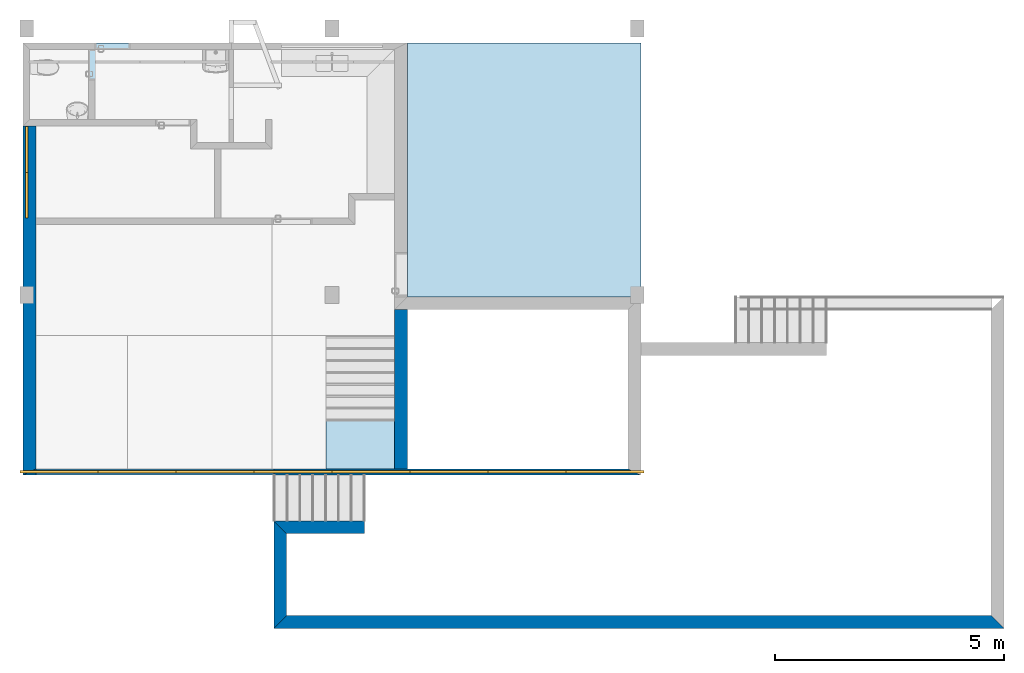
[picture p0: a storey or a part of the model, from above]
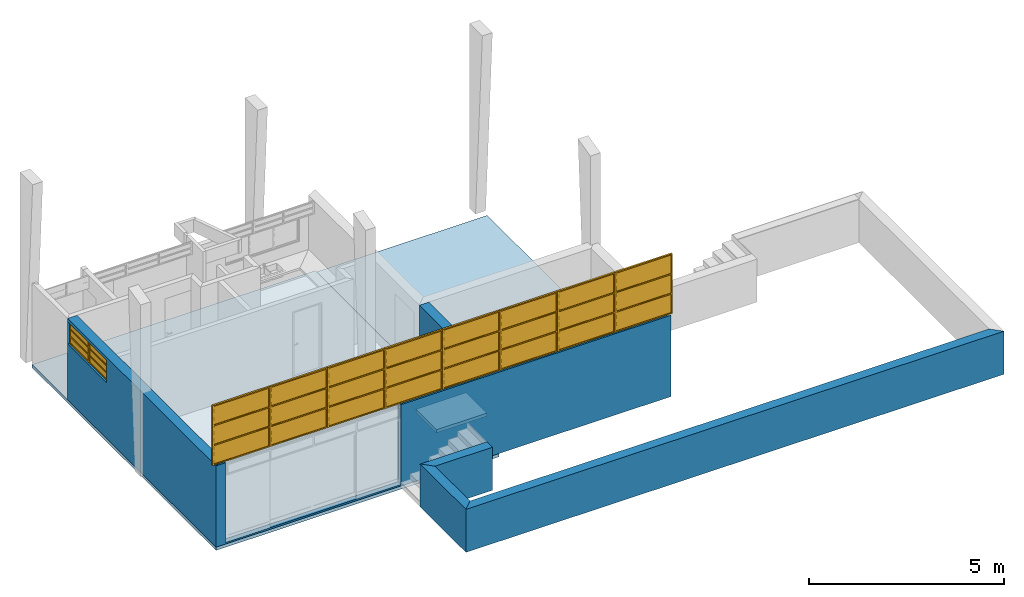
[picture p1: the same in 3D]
Properties of the parts of a building model (IFC2X3), part 1 of 2

# File
Description: ViewDefinition [CoordinationView_V2.0, QuantityTakeOffAddOnView], Option [Drawing Scale: 100.000000], Option [Elements to export: Entire project], Option [Partial Structure Display: Entire Model], Option [IFC Domain: All], Option [Structural Function: All Elements], Option [Convert Grid elements: On], Option [Convert IFC Annotations and ARCHICAD 2D elements: Off], Option [Convert 2D symbols of Doors and Windows: Off], Option [Export geometries that Participates in Collision Detection only: Off], Option [Split complex elements: Off], Option [Material Preservation: Explode where necessary], Option [Elements in Solid Element Operations: Extruded/revolved], Option [Elements with junctions: Extruded/revolved without junctions], Option [Slabs with slanted edge(s): Extruded], Option [IFC Site Location: At Project Origin], Option [Curtain Wall export mode: Container Element], Option [Railing export mode: Single Element], Option [Stair export mode: Container Element], Option [Properties To Export: All properties], Option [Space containment: Off], Option [Bounding Box: Off], Option [Geometry to type objects: Off], Option [Element Properties: Visible Only], Option [Building Material Properties: Off], Option [Element Parameters: Off], Option [Component Parameters: All], Option [IFC Base Quantities: On], Option [Door Window Parameters: On], Option [IFC Space boundaries: Off], Option [ARCHICAD Zone Categories as IFC Space classification data: Off], Option [Element Classifications: On]
File name: D:\Documents\FAU\ICs\PUB 2019-2020\PUB 2019-2020 Vanessa\Residência Olga Baeta.ifc
Time: 2021-04-10T14:19:01
Author: Architect
Organization: Building Designer Office
Written by: The EXPRESS Data Manager Version 5.02.0100.09 : 26 Sep 2013
Made in: IFC file generated by GRAPHISOFT ARCHICAD 23.0.0 BRA FULL Windows version (IFC add-on version: 3003 BRA FULL).
Authorization: The authorising person

# IfcSite, Local
RefLatitude: -23, -34, -3, -510000; RefLongitude: -46, -42, -34, -970000; RefElevation: 727000 mm
BaseQuantities - GrossPerimeter: 0 mm; GrossArea: 0 m2

# IfcBuilding, Construção
Classification: En_45_10_39 Casa isolada (NBR 15965-6)
BaseQuantities - GrossFloorArea: 216.281 m2

# IfcBuildingStorey (5)
In: Construção
Name | Elevation (mm) | NetHeight (mm) = GrossHeight (mm) = Height (mm) | GrossFloorArea (m2)
Fundação | -1500 | 1500 | 0
Pavimento Térreo | 0 | 1300 | 108.55
Pavimento Intermediário | 1300 | 1750 | 19.7248
Primeiro Pavimento | 3050 | 2750 | 88.0063
Pavimento Cobertura | 5800 | 2000 | 0

# IfcSpace: Circulação (3)
InteriorOrExteriorSpace: INTERNAL
Pset_SpaceCommon - Category: Circulação
AC_Pset_RenovationAndPhasing - Renovation Status: To Be Demolished
BaseQuantities - FinishFloorHeight: 0 mm
Name | In | LongName | Classification | Height (mm) = FinishCeilingHeight (mm) = ClearHeight (mm) | GrossFloorArea (m2) = NetFloorArea (m2) = SpaceNetFloorAreaBOMA (m2) = SpaceUsableFloorAreaBOMA (m2) = GrossCeilingArea (m2) = NetCeilingArea (m2) | GrossWallArea (m2) | NetWallArea (m2) | GrossPerimeter (mm) = NetPerimeter (mm) | GrossVolume (m3) | NetVolume (m3)
12 | Pavimento Térreo | Escada | Zoneamento (Classificação ARCHICAD); 4A 16 01 04 Escada (NBR 15965-6) | 5702.19 | 7.7988 | 12.9045 | 12.9045 | 11180 | 44.4702 | 37.4836
13 | Pavimento Térreo | Hall de entrada | Zoneamento (Classificação ARCHICAD); 4A 16 04 07 Saguão (NBR 15965-6) | 5702.19 | 6.8922 | 15.7845 | 11.9205 | 12500 | 39.3006 | 37.7929
11 | Primeiro Pavimento | Hall | Zoneamento (Classificação ARCHICAD); 4A 16 04 01 Corredor (NBR 15965-6) | 2550 | 13.7149 | 41.9729 | 31.8509 | 21300 | 34.973 | 33.7969

# IfcSpace: Área de serviço (4)
In: Pavimento Térreo
InteriorOrExteriorSpace: INTERNAL
Pset_SpaceCommon - Category: Área de serviço
AC_Pset_RenovationAndPhasing - Renovation Status: To Be Demolished
BaseQuantities - Height: 3050 mm; FinishCeilingHeight: 3050 mm; FinishFloorHeight: 0 mm; ClearHeight: 3050 mm
Name | LongName | Classification | GrossFloorArea (m2) = NetFloorArea (m2) = SpaceNetFloorAreaBOMA (m2) = SpaceUsableFloorAreaBOMA (m2) = GrossCeilingArea (m2) = NetCeilingArea (m2) | GrossWallArea (m2) | NetWallArea (m2) | GrossPerimeter (mm) = NetPerimeter (mm) | GrossVolume (m3) = NetVolume (m3)
03 | Lavanderia | Zoneamento (Classificação ARCHICAD); 4A 19 04 04 Lavanderia (NBR 15965-6) | 4.8622 | 22.284 | 17.643 | 9940 | 14.8297
02 | Cozinha | Zoneamento (Classificação ARCHICAD); 4A 19 01 25 Cozinha (NBR 15965-6) | 12.6781 | 39.7484 | 37.9214 | 17667.6 | 38.6681
04 | Banheiro de Serviço | Zoneamento (Classificação ARCHICAD); 4A 19 04 07 Banheiro Residencial (NBR 15965-6) | 1.9866 | 13.856 | 12.449 | 5660 | 6.05913
05 | Dormitório de serviço | Zoneamento (Classificação ARCHICAD); 4A 19 01 01 Dormitório (NBR 15965-6) | 7.579 | 28.741 | 27.124 | 11820 | 23.116

# IfcSpace: Área externa, 01
In: Pavimento Térreo
LongName: Garagem; InteriorOrExteriorSpace: INTERNAL; Classification: Zoneamento (Classificação ARCHICAD); 4A 19 04 13 Garagem (NBR 15965-6)
Pset_SpaceCommon - Category: Área externa
AC_Pset_RenovationAndPhasing - Renovation Status: Existing
BaseQuantities - Height: 3050 mm; FinishCeilingHeight: 3050 mm; FinishFloorHeight: 0 mm; ClearHeight: 3050 mm; GrossFloorArea: 28.305 m2; NetFloorArea: 28.305 m2; SpaceNetFloorAreaBOMA: 28.305 m2; SpaceUsableFloorAreaBOMA: 28.305 m2; GrossCeilingArea: 28.305 m2; NetCeilingArea: 28.305 m2; GrossWallArea: 26.084 m2; NetWallArea: 24.047 m2; GrossPerimeter: 21300 mm; NetPerimeter: 21300 mm; GrossVolume: 86.3303 m3; NetVolume: 86.3303 m3

# IfcSpace: Área social (3)
InteriorOrExteriorSpace: INTERNAL
Pset_SpaceCommon - Category: Área social
AC_Pset_RenovationAndPhasing - Renovation Status: To Be Demolished
BaseQuantities - FinishFloorHeight: 0 mm
Name | In | LongName | Classification | Height (mm) = FinishCeilingHeight (mm) = ClearHeight (mm) | GrossFloorArea (m2) = NetFloorArea (m2) = SpaceNetFloorAreaBOMA (m2) = SpaceUsableFloorAreaBOMA (m2) = GrossCeilingArea (m2) = NetCeilingArea (m2) | GrossWallArea (m2) | NetWallArea (m2) | GrossPerimeter (mm) = NetPerimeter (mm) | GrossVolume (m3) | NetVolume (m3)
07 | Pavimento Térreo | Sala de jantar | 4A 19 01 10 Sala de Jantar (NBR 15965-6); Zoneamento (Classificação ARCHICAD) | 5702.19 | 12.5388 | 19.3545 | 19.3545 | 15180 | 71.4986 | 68.5475
06 | Pavimento Térreo | Sala de estar | Zoneamento (Classificação ARCHICAD); 4A 19 01 07 Sala de Estar (NBR 15965-6) | 5702.19 | 15.0156 | 7.6785 | 7.6785 | 16140 | 85.6218 | 72.17
08 | Pavimento Intermediário | Escritório | Zoneamento (Classificação ARCHICAD); 4A 19 01 19 Escritório Residencial (NBR 15965-6) | 4201.52 | 16.7736 | 21.63 | 20.33 | 16600 | 70.4745 | 60.0031

# IfcSpace: Área íntima (6)
In: Primeiro Pavimento
InteriorOrExteriorSpace: INTERNAL
Pset_SpaceCommon - Category: Área íntima
AC_Pset_RenovationAndPhasing - Renovation Status: To Be Demolished
BaseQuantities - Height: 2550 mm; FinishCeilingHeight: 2550 mm; FinishFloorHeight: 0 mm; ClearHeight: 2550 mm
Name | LongName | Classification | GrossFloorArea (m2) = NetFloorArea (m2) = SpaceNetFloorAreaBOMA (m2) = SpaceUsableFloorAreaBOMA (m2) = GrossCeilingArea (m2) = NetCeilingArea (m2) | GrossWallArea (m2) | NetWallArea (m2) | GrossPerimeter (mm) = NetPerimeter (mm) | GrossVolume (m3) | NetVolume (m3)
15 | Dormitório 2 | Zoneamento (Classificação ARCHICAD); 4A 19 01 01 Dormitório (NBR 15965-6) | 12.098 | 37.4595 | 32.2125 | 14690 | 30.8498 | 30.8498
16 | Dormitório 3 | Zoneamento (Classificação ARCHICAD); 4A 19 01 01 Dormitório (NBR 15965-6) | 12.098 | 36.7241 | 31.4771 | 14690 | 30.8498 | 30.8498
09 | Dormitório 1 | Zoneamento (Classificação ARCHICAD); 4A 19 01 01 Dormitório (NBR 15965-6) | 18.0622 | 42.2238 | 36.9768 | 18220 | 46.0586 | 45.5784
14 | Banheiro 2 | Zoneamento (Classificação ARCHICAD); 4A 19 04 07 Banheiro Residencial (NBR 15965-6) | 5.5536 | 20.046 | 18.0914 | 9500 | 14.1617 | 14.125
17 | Dormitório 4 | Zoneamento (Classificação ARCHICAD); 4A 19 01 01 Dormitório (NBR 15965-6) | 11.1372 | 37.3616 | 32.1146 | 14940 | 28.3999 | 28.3999
10 | Banheiro 1 | Zoneamento (Classificação ARCHICAD); 4A 19 04 07 Banheiro Residencial (NBR 15965-6) | 4.694 | 18.6336 | 16.679 | 10560 | 11.9697 | 10.6472

# IfcBeam: Concreto Armado - Estrutural 100 x 300 (21)
In: Primeiro Pavimento
Description: Viga-interior-generico-in_loco-concreto_armado-100mm-300mm; Classification: 3E 12 06 02 00 Viga (NBR 15965-5); EF_20_10 Superstructure (Uniclass 2015); Viga (Classificação ARCHICAD); Material: Concreto Armado - Estrutural
AC_Pset_RenovationAndPhasing - Renovation Status: Existing
Pset_BeamCommon - LoadBearing: yes; IsExternal: no; Reference: Concreto Armado - Estrutural 100 x 300
Component Properties - Component 1, Tipo de Componente: Núcleo
BaseQuantities - Width: 100 mm; Depth: 300 mm; CrossSectionArea: 0.03 m2
Component Quantities - Component 1, Espessura da Camada: 100 mm; Component 1, Altura do Componente Retangular: 300 mm; Component 1, Largura do Componente Retangular: 100 mm; Component 1, Área de Seção Transversal do Componente: 0.03 m2
Name | Component 1, Carbono Incorporado | Component 1, Energia Incorporada (MJ) | NetSurfaceAreaExtrudedSides (m2) = OuterSurfaceArea (m2) | Length (mm) | TotalSurfaceArea (m2) = GrossSurfaceArea (m2) = NetSurfaceArea (m2) | GrossVolume (m3) = NetVolume (m3) = Component 1, Volume da Camada/ Componente (m3) | Component 1, Massa (kg) | Component 1, Área Projetada Componente/Camada (m2)
V13 | 218.497 (kgCO₂) | 2103.71 | 10.032 | 12540 | 10.092 | 0.3762 | 902.88 | 3.762
15 x V13 | 225.467 (kgCO₂) | 2170.81 | 10.352 | 12940 | 10.412 | 0.3882 | 931.68 | 3.882
2 x V13 | 97.5744 (kgCO₂) | 939.456 | 4.48 | 5600 | 4.54 | 0.168 | 403.2 | 1.68
V13 | 66.5597 (kgCO₂) | 640.843 | 3.056 | 3820 | 3.116 | 0.1146 | 275.04 | 1.146
V13 | 64.8173 (kgCO₂) | 624.067 | 2.976 | 3720 | 3.036 | 0.1116 | 267.84 | 1.116
V13 | 9.23472 (kgCO₂) | 88.9128 | 0.424 | 530 | 0.484 | 0.0159 | 38.16 | 0.159

# IfcBeam: Concreto Armado - Estrutural 220 x 360 (12)
In: Pavimento Cobertura
Description: Viga-interior-generico-in_loco-concreto_armado-220mm-360mm; Classification: 3E 12 06 02 00 Viga (NBR 15965-5); EF_20_10 Superstructure (Uniclass 2015); Viga (Classificação ARCHICAD); Material: Concreto Armado - Estrutural
AC_Pset_RenovationAndPhasing - Renovation Status: Existing
Pset_BeamCommon - LoadBearing: yes; IsExternal: no; Reference: Concreto Armado - Estrutural 220 x 360
Component Properties - Component 1, Tipo de Componente: Núcleo
BaseQuantities - Length: 6370 mm; Width: 220 mm; Depth: 360 mm; CrossSectionArea: 0.0792 m2
Component Quantities - Component 1, Espessura da Camada: 220 mm; Component 1, Altura do Componente Retangular: 360 mm; Component 1, Largura do Componente Retangular: 220 mm; Component 1, Área de Seção Transversal do Componente: 0.0792 m2
Name | Component 1, Carbono Incorporado | Component 1, Energia Incorporada (MJ) | NetSurfaceAreaExtrudedSides (m2) = OuterSurfaceArea (m2) | TotalSurfaceArea (m2) = GrossSurfaceArea (m2) = NetSurfaceArea (m2) | GrossVolume (m3) = NetVolume (m3) = Component 1, Volume da Camada/ Componente (m3) | Component 1, Massa (kg) | Component 1, Área Projetada Componente/Camada (m2)
10 x V13 | 283.622 (kgCO₂) | 2730.75 | 7.03326 | 7.19166 | 0.488331 | 1171.99 | 2.23585
2 x V13 | 282.665 (kgCO₂) | 2721.53 | 7.08492 | 7.24332 | 0.486683 | 1168.04 | 2.22008

# IfcBeam: Concreto Armado - Estrutural 250 x 300 (5)
In: Primeiro Pavimento
Description: viga-interior-concreto_armado-250mm-300mm; Classification: 3E 12 06 02 00 Viga (NBR 15965-5); EF_20_10 Superstructure (Uniclass 2015); Viga (Classificação ARCHICAD); Material: Concreto Armado - Estrutural
AC_Pset_RenovationAndPhasing - Renovation Status: Existing
Pset_BeamCommon - LoadBearing: yes; IsExternal: no; Reference: Concreto Armado - Estrutural 250 x 300
Component Properties - Component 1, Tipo de Componente: Núcleo
BaseQuantities - Width: 250 mm; Depth: 300 mm; CrossSectionArea: 0.075 m2
Component Quantities - Component 1, Espessura da Camada: 250 mm; Component 1, Altura do Componente Retangular: 300 mm; Component 1, Largura do Componente Retangular: 250 mm; Component 1, Área de Seção Transversal do Componente: 0.075 m2
Name | Component 1, Carbono Incorporado | Component 1, Energia Incorporada (MJ) | NetSurfaceAreaExtrudedSides (m2) = OuterSurfaceArea (m2) | Length (mm) | TotalSurfaceArea (m2) = GrossSurfaceArea (m2) = NetSurfaceArea (m2) | GrossVolume (m3) = NetVolume (m3) = Component 1, Volume da Camada/ Componente (m3) | Component 1, Massa (kg) | Component 1, Área Projetada Componente/Camada (m2)
V13 | 583.268 (kgCO₂) | 5615.77 | 14.729 | 13640 | 14.879 | 1.00425 | 2410.2 | 4.092
2 x V13 | 233.162 (kgCO₂) | 2244.91 | 5.86921 | 5530.17 | 6.01921 | 0.401451 | 963.481 | 1.65362
V13 | 567.083 (kgCO₂) | 5459.94 | 14.2733 | 13420.2 | 14.4233 | 0.976383 | 2343.32 | 4.02062
V13 | 164.597 (kgCO₂) | 1584.75 | 4.17862 | 4000 | 4.32862 | 0.283397 | 680.152 | 1.2

# IfcBeam: Concreto Armado - Estrutural 300 x 200 (6)
In: Pavimento Cobertura
Description: Viga-interior-generico-in_loco-concreto_armado-300mm-200mm; Classification: 3E 12 06 02 00 Viga (NBR 15965-5); EF_20_10 Superstructure (Uniclass 2015); Viga (Classificação ARCHICAD); Material: Concreto Armado - Estrutural
AC_Pset_RenovationAndPhasing - Renovation Status: Existing
Pset_BeamCommon - LoadBearing: yes; IsExternal: no; Reference: Concreto Armado - Estrutural 300 x 200
Component Properties - Component 1, Tipo de Componente: Núcleo
BaseQuantities - Width: 300 mm; Depth: 200 mm; CrossSectionArea: 0.06 m2
Component Quantities - Component 1, Espessura da Camada: 300 mm; Component 1, Altura do Componente Retangular: 200 mm; Component 1, Largura do Componente Retangular: 300 mm; Component 1, Área de Seção Transversal do Componente: 0.06 m2
Name | Component 1, Carbono Incorporado | Component 1, Energia Incorporada (MJ) | NetSurfaceAreaExtrudedSides (m2) = OuterSurfaceArea (m2) | Length (mm) | TotalSurfaceArea (m2) = GrossSurfaceArea (m2) = NetSurfaceArea (m2) | GrossVolume (m3) = NetVolume (m3) = Component 1, Volume da Camada/ Componente (m3) | Component 1, Massa (kg) | Component 1, Área Projetada Componente/Camada (m2)
3 x V10 | 81.3778 (kgCO₂) | 783.514 | 2.33522 | 2761.23 | 2.45522 | 0.140113 | 336.272 | 0.467045
3 x V11 | 271.547 (kgCO₂) | 2614.48 | 7.79232 | 8218.33 | 7.91232 | 0.467539 | 1122.09 | 1.55846

# IfcBeam: Concreto Armado - Estrutural 600 x 150 (4)
In: Pavimento Cobertura
Description: Viga-interior-generico-in_loco-concreto_armado-600mm-150mm; Classification: 3E 12 06 02 00 Viga (NBR 15965-5); EF_20_10 Superstructure (Uniclass 2015); Viga (Classificação ARCHICAD); Material: Concreto Armado - Estrutural
AC_Pset_RenovationAndPhasing - Renovation Status: Existing
Pset_BeamCommon - LoadBearing: yes; IsExternal: no; Reference: Concreto Armado - Estrutural 600 x 150
Component Properties - Component 1, Tipo de Componente: Núcleo
BaseQuantities - Width: 600 mm; Depth: 150 mm; CrossSectionArea: 0.09 m2
Component Quantities - Component 1, Espessura da Camada: 600 mm; Component 1, Altura do Componente Retangular: 150 mm; Component 1, Largura do Componente Retangular: 600 mm; Component 1, Área de Seção Transversal do Componente: 0.09 m2
Name | Component 1, Carbono Incorporado | Component 1, Energia Incorporada (MJ) | NetSurfaceAreaExtrudedSides (m2) = OuterSurfaceArea (m2) | Length (mm) | TotalSurfaceArea (m2) = GrossSurfaceArea (m2) = NetSurfaceArea (m2) | GrossVolume (m3) = NetVolume (m3) = Component 1, Volume da Camada/ Componente (m3) | Component 1, Massa (kg) | Component 1, Área Projetada Componente/Camada (m2)
2 x V19 | 157.211 (kgCO₂) | 1513.64 | 4.41566 | 3112.32 | 4.59566 | 0.27068 | 649.632 | 0.451133
2 x V21 | 442.464 (kgCO₂) | 4260.09 | 12.6013 | 8569.42 | 12.7813 | 0.761819 | 1828.37 | 1.2697

# IfcBeam: Concreto Armado - Estrutural 850 x 150 (2)
In: Pavimento Cobertura
Description: Viga-interior-generico-in_loco-concreto_armado-850mm-150mm; Classification: 3E 12 06 02 00 Viga (NBR 15965-5); EF_20_10 Superstructure (Uniclass 2015); Viga (Classificação ARCHICAD); Material: Concreto Armado - Estrutural
AC_Pset_RenovationAndPhasing - Renovation Status: Existing
Pset_BeamCommon - LoadBearing: yes; IsExternal: no; Reference: Concreto Armado - Estrutural 850 x 150
Component Properties - Component 1, Tipo de Componente: Núcleo
BaseQuantities - Width: 850 mm; Depth: 150 mm; CrossSectionArea: 0.1275 m2
Component Quantities - Component 1, Espessura da Camada: 850 mm; Component 1, Altura do Componente Retangular: 150 mm; Component 1, Largura do Componente Retangular: 850 mm; Component 1, Área de Seção Transversal do Componente: 0.1275 m2
Name | Component 1, Carbono Incorporado | Component 1, Energia Incorporada (MJ) | NetSurfaceAreaExtrudedSides (m2) = OuterSurfaceArea (m2) | Length (mm) | TotalSurfaceArea (m2) = GrossSurfaceArea (m2) = NetSurfaceArea (m2) | GrossVolume (m3) = NetVolume (m3) = Component 1, Volume da Camada/ Componente (m3) | Component 1, Massa (kg) | Component 1, Área Projetada Componente/Camada (m2)
V18 | 626.825 (kgCO₂) | 6035.13 | 16.7938 | 8569.42 | 17.0488 | 1.07924 | 2590.18 | 1.2697
V17 | 222.716 (kgCO₂) | 2144.33 | 5.87957 | 3112.32 | 6.13457 | 0.383463 | 920.312 | 0.451133

# IfcBeam: Madeiramento - Cobertura 50 x 10 (40)
In: Pavimento Cobertura
Description: ripa--generico-generico-madeira-50mm-10mm; Classification: Viga (Classificação ARCHICAD); EF_30_10 Roofs (Uniclass 2015); 3E 14 04 02 Telhado (NBR 15965-5); Material: Madeiramento - Cobertura
AC_Pset_RenovationAndPhasing - Renovation Status: Existing
Pset_BeamCommon - LoadBearing: yes; IsExternal: yes; Reference: Madeiramento - Cobertura 50 x 10
Component Properties - Component 1, Tipo de Componente: Núcleo
BaseQuantities - Length: 13640 mm; Width: 50 mm; Depth: 10 mm; CrossSectionArea: 0.0005 m2
Component Quantities - Component 1, Área Projetada Componente/Camada: 0.1364 m2; Component 1, Espessura da Camada: 50 mm; Component 1, Altura do Componente Retangular: 10 mm; Component 1, Largura do Componente Retangular: 50 mm; Component 1, Área de Seção Transversal do Componente: 0.0005 m2
Name | Component 1, Carbono Incorporado | Component 1, Energia Incorporada (MJ) | NetSurfaceAreaExtrudedSides (m2) = OuterSurfaceArea (m2) | TotalSurfaceArea (m2) = GrossSurfaceArea (m2) = NetSurfaceArea (m2) | GrossVolume (m3) = NetVolume (m3) = Component 1, Volume da Camada/ Componente (m3) | Component 1, Massa (kg)
2 x Ripa | 1.2231 (kgCO₂) | 33.975 | 1.6308 | 1.6318 | 0.006795 | 3.3975
38 x Ripa | 1.2276 (kgCO₂) | 34.1 | 1.6368 | 1.6378 | 0.00682 | 3.41

# IfcBeam: Madeiramento - Cobertura 50 x 60 (62)
In: Pavimento Cobertura
Description: caibro--generico-generico-madeira-50mm-60mm; Classification: Viga (Classificação ARCHICAD); EF_30_10 Roofs (Uniclass 2015); 3E 14 04 02 Telhado (NBR 15965-5); Material: Madeiramento - Cobertura
AC_Pset_RenovationAndPhasing - Renovation Status: Existing
Pset_BeamCommon - LoadBearing: yes; IsExternal: yes; Reference: Madeiramento - Cobertura 50 x 60
Component Properties - Component 1, Tipo de Componente: Núcleo
BaseQuantities - Width: 50 mm; Depth: 60 mm; CrossSectionArea: 0.003 m2
Component Quantities - Component 1, Espessura da Camada: 50 mm; Component 1, Altura do Componente Retangular: 60 mm; Component 1, Largura do Componente Retangular: 50 mm; Component 1, Área de Seção Transversal do Componente: 0.003 m2
Name | Component 1, Carbono Incorporado | Component 1, Energia Incorporada (MJ) | NetSurfaceAreaExtrudedSides (m2) = OuterSurfaceArea (m2) | Length (mm) | TotalSurfaceArea (m2) = GrossSurfaceArea (m2) = NetSurfaceArea (m2) | GrossVolume (m3) = NetVolume (m3) = Component 1, Volume da Camada/ Componente (m3) | Component 1, Massa (kg) | Component 1, Área Projetada Componente/Camada (m2)
10 x Caibro | 3.07809 (kgCO₂) | 85.5024 | 1.23852 | 5795 | 1.24452 | 0.0171005 | 8.55024 | 0.345126
Caibro | 4.59893 (kgCO₂) | 127.748 | 1.87364 | 8549.02 | 1.87964 | 0.0255496 | 12.7748 | 0.512492
2 x Caibro | 1.65345 (kgCO₂) | 45.9291 | 0.673626 | 3094.42 | 0.679626 | 0.00918581 | 4.59291 | 0.185216
24 x Caibro | 4.61782 (kgCO₂) | 128.273 | 1.88133 | 8566.48 | 1.88733 | 0.0256545 | 12.8273 | 0.513091
24 x Caibro | 1.67233 (kgCO₂) | 46.4537 | 0.68132 | 3111.87 | 0.68732 | 0.00929073 | 4.64537 | 0.185815
Caibro | 4.59893 (kgCO₂) | 127.748 | 1.87364 | 8549.02 | 1.87964 | 0.0255496 | 12.7748 | 0.512493

# IfcBuildingElementPart (66)
Name | In | Material | Carbono Incorporado | Energia Incorporada (MJ) | Tipo de Componente | Massa (kg) | Área Projetada Componente/Camada (m2) | Espessura da Camada (mm) = Largura do Componente Retangular (mm) | Altura do Componente Retangular (mm) | Área de Seção Transversal do Componente (m2) | Volume da Camada/ Componente (m3)
Reboco | Pavimento Térreo | Reboco | 19.7589 (kgCO₂) | 273.585 | Acabamento | 151.992 | 5.84584 | 20 | 1350 | 0.027 | 0.116917
Tijolo - Estrutural | Pavimento Térreo | Tijolo - Estrutural | 507.414 (kgCO₂) | 6342.67 | Núcleo | 2114.22 | 5.87284 | 240 | 1350 | 0.324 | 1.40948
Reboco | Pavimento Térreo | Reboco | 20.9453 (kgCO₂) | 290.012 | Acabamento | 161.118 | 6.19684 | 20 | 1350 | 0.027 | 0.123937
Reboco (1) | Primeiro Pavimento | Reboco (1) | 51.4628 (kgCO₂) | 712.562 | Acabamento | 395.868 | 15.2445 | 20 | 3211.87 | 0.0642375 | 0.304514
Tijolo - Estrutural (1) | Primeiro Pavimento | Tijolo - Estrutural (1) | 556.162 (kgCO₂) | 6952.02 | Núcleo | 2317.34 | 15.5437 | 100 | 3211.87 | 0.321187 | 1.54489
Reboco (1) | Primeiro Pavimento | Reboco (1) | 50.3556 (kgCO₂) | 697.231 | Acabamento | 387.35 | 14.9164 | 20 | 3211.87 | 0.0642375 | 0.297962
Reboco (1) | Primeiro Pavimento | Reboco (1) | 69.5168 (kgCO₂) | 962.541 | Acabamento | 534.745 | 20.6426 | 20 | 3211.87 | 0.0642375 | 0.411342
Tijolo - Estrutural (1) | Primeiro Pavimento | Tijolo - Estrutural (1) | 769.641 (kgCO₂) | 9620.51 | Núcleo | 3206.84 | 21.3789 | 100 | 3211.87 | 0.321187 | 2.13789
Reboco (1) | Primeiro Pavimento | Reboco (1) | 72.2607 (kgCO₂) | 1000.53 | Acabamento | 555.852 | 21.3789 | 20 | 3211.87 | 0.0642375 | 0.427578
Reboco (1) | Primeiro Pavimento | Reboco (1) | 26.5744 (kgCO₂) | 367.953 | Acabamento | 204.418 | 7.86881 | 20 | 3211.87 | 0.0642375 | 0.157245
Tijolo - Estrutural (1) | Primeiro Pavimento | Tijolo - Estrutural (1) | 301.648 (kgCO₂) | 3770.6 | Núcleo | 1256.87 | 8.4139 | 100 | 3211.87 | 0.321187 | 0.837911
Reboco (1) | Primeiro Pavimento | Reboco (1) | 28.6665 (kgCO₂) | 396.921 | Acabamento | 220.512 | 8.48822 | 20 | 3211.87 | 0.0642375 | 0.169624
2 x Reboco (1) | Primeiro Pavimento | Reboco (1) | 38.1169 (kgCO₂) | 527.772 | Acabamento | 293.207 | 11.2772 | 20 | 3211.87 | 0.0642375 | 0.225544
Tijolo - Estrutural (1) | Primeiro Pavimento | Tijolo - Estrutural (1) | 409.952 (kgCO₂) | 5124.4 | Núcleo | 1708.13 | 11.3876 | 100 | 3211.87 | 0.321187 | 1.13876
Reboco (1) | Primeiro Pavimento | Reboco (1) | 48.5939 (kgCO₂) | 672.839 | Acabamento | 373.8 | 14.3769 | 20 | 3211.87 | 0.0642375 | 0.287538
Tijolo - Estrutural (1) | Primeiro Pavimento | Tijolo - Estrutural (1) | 535.947 (kgCO₂) | 6699.34 | Núcleo | 2233.11 | 14.8874 | 100 | 3211.87 | 0.321187 | 1.48874
Reboco (1) | Primeiro Pavimento | Reboco (1) | 49.3738 (kgCO₂) | 683.638 | Acabamento | 379.799 | 14.6076 | 20 | 3211.87 | 0.0642375 | 0.292153
Reboco (1) | Primeiro Pavimento | Reboco (1) | 18.3303 (kgCO₂) | 253.804 | Acabamento | 141.002 | 5.42315 | 20 | 3211.87 | 0.0642375 | 0.108463
Tijolo - Estrutural (1) | Primeiro Pavimento | Tijolo - Estrutural (1) | 208.661 (kgCO₂) | 2608.26 | Núcleo | 869.421 | 5.79614 | 100 | 3211.87 | 0.321187 | 0.579614
Reboco (1) | Primeiro Pavimento | Reboco (1) | 19.621 (kgCO₂) | 271.676 | Acabamento | 150.931 | 5.80504 | 20 | 3211.87 | 0.0642375 | 0.116101
Reboco (1) | Primeiro Pavimento | Reboco (1) | 26.8015 (kgCO₂) | 371.097 | Acabamento | 206.165 | 7.93895 | 20 | 3211.87 | 0.0642375 | 0.158589
Tijolo - Estrutural (1) | Primeiro Pavimento | Tijolo - Estrutural (1) | 286.011 (kgCO₂) | 3575.14 | Núcleo | 1191.71 | 7.99213 | 100 | 3211.87 | 0.321187 | 0.794476
Reboco (1) | Primeiro Pavimento | Reboco (1) | 26.3337 (kgCO₂) | 364.621 | Acabamento | 202.567 | 7.80026 | 20 | 3211.87 | 0.0642375 | 0.155821
Reboco (1) | Primeiro Pavimento | Reboco (1) | 24.5278 (kgCO₂) | 339.615 | Acabamento | 188.675 | 7.26484 | 20 | 3211.87 | 0.0642375 | 0.145135
Tijolo - Estrutural (1) | Primeiro Pavimento | Tijolo - Estrutural (1) | 253.282 (kgCO₂) | 3166.03 | Núcleo | 1055.34 | 7.07464 | 100 | 3211.87 | 0.321187 | 0.703562
Reboco (1) | Primeiro Pavimento | Reboco (1) | 23.0209 (kgCO₂) | 318.751 | Acabamento | 177.084 | 6.81842 | 20 | 3211.87 | 0.0642375 | 0.136218
Reboco (1) | Primeiro Pavimento | Reboco (1) | 20.0006 (kgCO₂) | 276.931 | Acabamento | 153.851 | 5.91733 | 20 | 3211.87 | 0.0642375 | 0.118347
Tijolo - Estrutural (1) | Primeiro Pavimento | Tijolo - Estrutural (1) | 212.739 (kgCO₂) | 2659.24 | Núcleo | 886.412 | 5.90941 | 100 | 3211.87 | 0.321187 | 0.590941
Reboco (1) | Primeiro Pavimento | Reboco (1) | 18.7118 (kgCO₂) | 259.087 | Acabamento | 143.937 | 5.53605 | 20 | 3211.87 | 0.0642375 | 0.110721
Reboco (1) | Primeiro Pavimento | Reboco (1) | 7.34301 (kgCO₂) | 101.673 | Acabamento | 56.4847 | 2.17419 | 20 | 3211.87 | 0.0642375 | 0.0434498
Tijolo - Estrutural (1) | Primeiro Pavimento | Tijolo - Estrutural (1) | 68.6854 (kgCO₂) | 858.567 | Núcleo | 286.189 | 1.91541 | 100 | 3211.87 | 0.321187 | 0.190793
Reboco (1) | Primeiro Pavimento | Reboco (1) | 7.27425 (kgCO₂) | 100.72 | Acabamento | 55.9558 | 2.15384 | 20 | 3211.87 | 0.0642375 | 0.0430429
Reboco (1) | Primeiro Pavimento | Reboco (1) | 7.54194 (kgCO₂) | 104.427 | Acabamento | 58.0149 | 2.23134 | 20 | 3211.87 | 0.0642375 | 0.0446268
Tijolo - Estrutural (1) | Primeiro Pavimento | Tijolo - Estrutural (1) | 78.7207 (kgCO₂) | 984.008 | Núcleo | 328.003 | 2.18668 | 100 | 3211.87 | 0.321187 | 0.218668
Reboco (1) | Primeiro Pavimento | Reboco (1) | 6.63124 (kgCO₂) | 91.8171 | Acabamento | 51.0095 | 1.9619 | 20 | 3211.87 | 0.0642375 | 0.0392381
Reboco (1) | Primeiro Pavimento | Reboco (1) | 25.5089 (kgCO₂) | 353.2 | Acabamento | 196.222 | 7.55544 | 20 | 3211.87 | 0.0642375 | 0.15094
Tijolo - Estrutural (1) | Primeiro Pavimento | Tijolo - Estrutural (1) | 267.039 (kgCO₂) | 3337.99 | Núcleo | 1112.66 | 7.45889 | 100 | 3211.87 | 0.321187 | 0.741775
Reboco (1) | Primeiro Pavimento | Reboco (1) | 24.9329 (kgCO₂) | 345.225 | Acabamento | 191.792 | 7.38473 | 20 | 3211.87 | 0.0642375 | 0.147532
Reboco (1) | Primeiro Pavimento | Reboco (1) | 2.02544 (kgCO₂) | 28.0446 | Acabamento | 15.5803 | 0.599244 | 20 | 3211.87 | 0.0642375 | 0.0119849
Tijolo - Estrutural (1) | Primeiro Pavimento | Tijolo - Estrutural (1) | 23.202 (kgCO₂) | 290.025 | Núcleo | 96.6749 | 0.644499 | 100 | 3211.87 | 0.321187 | 0.0644499
Reboco (1) | Primeiro Pavimento | Reboco (1) | 2.93816 (kgCO₂) | 40.6823 | Acabamento | 22.6013 | 0.869279 | 20 | 3211.87 | 0.0642375 | 0.0173856
Reboco (1) | Primeiro Pavimento | Reboco (1) | 10.14 (kgCO₂) | 140.401 | Acabamento | 78.0003 | 3.00001 | 20 | 3211.87 | 0.0642375 | 0.0600002
Tijolo - Estrutural (1) | Primeiro Pavimento | Tijolo - Estrutural (1) | 118.336 (kgCO₂) | 1479.2 | Núcleo | 493.065 | 3.2871 | 100 | 3211.87 | 0.321187 | 0.32871
Reboco (1) | Primeiro Pavimento | Reboco (1) | 11.9837 (kgCO₂) | 165.928 | Acabamento | 92.1822 | 3.54547 | 20 | 3211.87 | 0.0642375 | 0.0709094
Reboco (1) | Primeiro Pavimento | Reboco (1) | 9.58675 (kgCO₂) | 132.74 | Acabamento | 73.7442 | 2.8406 | 20 | 3211.87 | 0.0642375 | 0.0567263
Tijolo - Estrutural (1) | Primeiro Pavimento | Tijolo - Estrutural (1) | 106.365 (kgCO₂) | 1329.56 | Núcleo | 443.186 | 2.97676 | 100 | 3211.87 | 0.321187 | 0.295457
Reboco (1) | Primeiro Pavimento | Reboco (1) | 9.0701 (kgCO₂) | 125.586 | Acabamento | 69.77 | 2.68765 | 20 | 3211.87 | 0.0642375 | 0.0536692
Reboco (1) | Primeiro Pavimento | Reboco (1) | 14.6991 (kgCO₂) | 203.526 | Acabamento | 113.07 | 4.34885 | 20 | 3211.87 | 0.0642375 | 0.0869769
Tijolo - Estrutural (1) | Primeiro Pavimento | Tijolo - Estrutural (1) | 157.435 (kgCO₂) | 1967.94 | Núcleo | 655.981 | 4.37321 | 100 | 3211.87 | 0.321187 | 0.437321
Reboco (1) | Primeiro Pavimento | Reboco (1) | 14.4128 (kgCO₂) | 199.562 | Acabamento | 110.868 | 4.26415 | 20 | 3211.87 | 0.0642375 | 0.0852829
2 x Reboco (1) | Primeiro Pavimento | Reboco (1) | 9.50169 (kgCO₂) | 131.562 | Acabamento | 73.0899 | 2.81115 | 20 | 4250 | 0.085 | 0.056223
Tijolo - Estrutural (1) | Primeiro Pavimento | Tijolo - Estrutural (1) | 61.9902 (kgCO₂) | 774.877 | Núcleo | 258.292 | 2.86992 | 60 | 4250 | 0.255 | 0.172195
Reboco (1) | Primeiro Pavimento | Reboco (1) | 3.4206 (kgCO₂) | 47.3622 | Acabamento | 26.3123 | 1.01201 | 20 | 4250 | 0.085 | 0.0202403
Tijolo - Estrutural (1) | Primeiro Pavimento | Tijolo - Estrutural (1) | 22.9026 (kgCO₂) | 286.283 | Núcleo | 95.4276 | 1.06031 | 60 | 4250 | 0.255 | 0.0636184
Reboco (1) | Primeiro Pavimento | Reboco (1) | 4.39496 (kgCO₂) | 60.8532 | Acabamento | 33.8074 | 1.30028 | 20 | 4250 | 0.085 | 0.0260057
Reboco (1) | Primeiro Pavimento | Reboco (1) | 13.9236 (kgCO₂) | 192.789 | Acabamento | 107.105 | 4.12375 | 20 | 3211.87 | 0.0642375 | 0.0823883
Tijolo - Estrutural (1) | Primeiro Pavimento | Tijolo - Estrutural (1) | 147.521 (kgCO₂) | 1844.01 | Núcleo | 614.67 | 4.11924 | 100 | 3211.87 | 0.321187 | 0.40978
Reboco (1) | Primeiro Pavimento | Reboco (1) | 13.1272 (kgCO₂) | 181.761 | Acabamento | 100.978 | 3.88783 | 20 | 3211.87 | 0.0642375 | 0.0776758
Reboco (1) | Primeiro Pavimento | Reboco (1) | 2.49922 (kgCO₂) | 34.6046 | Acabamento | 19.2248 | 0.740163 | 20 | 3211.87 | 0.0642375 | 0.0147883
Tijolo - Estrutural (1) | Primeiro Pavimento | Tijolo - Estrutural (1) | 24.0823 (kgCO₂) | 301.029 | Núcleo | 100.343 | 0.738668 | 100 | 3211.87 | 0.321187 | 0.0668952
Reboco (1) | Primeiro Pavimento | Reboco (1) | 1.44423 (kgCO₂) | 19.997 | Acabamento | 11.1094 | 0.477 | 20 | 3211.87 | 0.0642375 | 0.00854571
Reboco (1) | Primeiro Pavimento | Reboco (1) | 2.02896 (kgCO₂) | 28.0933 | Acabamento | 15.6074 | 0.600285 | 20 | 3211.87 | 0.0642375 | 0.0120057
Tijolo - Estrutural (1) | Primeiro Pavimento | Tijolo - Estrutural (1) | 14.7865 (kgCO₂) | 184.832 | Núcleo | 61.6105 | 0.410737 | 100 | 3211.87 | 0.321187 | 0.0410737
Reboco (1) | Primeiro Pavimento | Reboco (1) | 1.06163 (kgCO₂) | 14.6995 | Acabamento | 8.16642 | 0.314093 | 20 | 3211.87 | 0.0642375 | 0.00628186

# IfcBuildingElementProxy: IfcBuildingElementProxy (3)
Material: Concreto - Contra Piso
AC_Pset_RenovationAndPhasing - Renovation Status: Existing
Name | In | Component 1, Carbono Incorporado | Component 1, Energia Incorporada (MJ) | Component 1, Massa (kg) | Component 1, Volume da Camada/ Componente (m3)
RISER-010 | Pavimento Térreo | 0.838776 (kgCO₂) | 5.80088 | 7.83902 | 0.00435501
TREAD-010 | Pavimento Térreo | 6.29802 (kgCO₂) | 43.5564 | 58.86 | 0.0327
TREAD-011 | Pavimento Intermediário | 4.38864 (kgCO₂) | 30.3514 | 41.0154 | 0.0227863

# IfcColumn: Concreto Armado - Estrutural 650 x 300 (6)
In: Pavimento Térreo
Description: Pilar-retangular_secao_variavel-generico-in_loco-concreto_armado-300mm-300_a_650mm; Classification: 3E 12 10 02 02 Pilar (NBR 15965-5); EF_20_10 Superstructure (Uniclass 2015); Pilar (Classificação ARCHICAD); Material: Concreto Armado - Estrutural
AC_Pset_RenovationAndPhasing - Renovation Status: Existing
Pset_ColumnCommon - LoadBearing: yes; IsExternal: yes; Reference: Concreto Armado - Estrutural 650 x 300
Component Properties - Component 1, Tipo de Componente: Núcleo
Name | Component 1, Carbono Incorporado | Component 1, Energia Incorporada (MJ) | NetVolume (m3) = GrossVolume (m3) = Component 1, Volume da Camada/ Componente (m3) | Length (mm) | Component 1, Massa (kg)
Pilar-01 | 480.031 (kgCO₂) | 4621.79 | 0.8265 | 5800 | 1983.6
Pilar-02 | 480.031 (kgCO₂) | 4621.79 | 0.8265 | 5800 | 1983.6
Pilar-03 | 480.031 (kgCO₂) | 4621.79 | 0.8265 | 5800 | 1983.6
Pilar-05 | 443.568 (kgCO₂) | 4270.71 | 0.763719 | 5552.55 | 1832.92
Pilar-06 | 443.568 (kgCO₂) | 4270.71 | 0.763719 | 5552.55 | 1832.92
Pilar-04 | 443.568 (kgCO₂) | 4270.71 | 0.763719 | 5552.55 | 1832.92

# IfcCovering: Concreto Armado - Não Estrutural 50 (2)
In: Primeiro Pavimento
Type - PredefinedType: CEILING
Description: Forro-interior-generico-in_loco-concreto_armado-50mm; Classification: EF_30_20 Floors (Uniclass 2015); 3E 16 04 Forros (NBR 15965-5); Forro (Classificação ARCHICAD); Material: A--FORR-RVST-E-
Pset_CoveringCommon - Material: Concreto Armado
Pset_ManufacturerTypeInformation - ProductionYear: DD/MM/YYYY
Component Properties - Component 1, Tipo de Componente: Nenhum
Component Quantities - Component 1, Espessura da Camada: 50 mm
Name | Renovation Status | Component 1, Carbono Incorporado | Component 1, Energia Incorporada (MJ) | GrossArea (m2) = NetArea (m2) = Component 1, Área Projetada Componente/Camada (m2) | Component 1, Massa (kg) | Component 1, Volume da Camada/ Componente (m3)
Forro-02 | Existing | 2471.32 (kgCO₂) | 23794.1 | 85.1032 | 10212.1 | 4.25502
Forro-01 | To Be Demolished | 104.01 (kgCO₂) | 1001.42 | 3.5816 | 429.792 | 0.17908

# IfcCovering: GENÉRICO - REV. INTERNO 50 (19)
Type - PredefinedType: FLOORING
Description: Piso-interior-generico-in_loco-generico-50mm; Classification: EF_30_20 Floors (Uniclass 2015); 3E 16 02 04 Revestimento de piso (NBR 15965-5); Assoalho (Classificação ARCHICAD); Material: GENÉRICO - REV. INTERNO
Pset_CoveringCommon - Material: GENÉRICO - REV. INTERNO
Pset_ManufacturerTypeInformation - ProductionYear: DD/MM/YYYY
AC_Pset_RenovationAndPhasing - Renovation Status: Existing
Component Properties - Component 1, Tipo de Componente: Nenhum
Component Quantities - Component 1, Espessura da Camada: 50 mm
Name | In | Component 1, Carbono Incorporado | Component 1, Energia Incorporada (MJ) | GrossArea (m2) = NetArea (m2) = Component 1, Área Projetada Componente/Camada (m2) | Component 1, Massa (kg) | Component 1, Volume da Camada/ Componente (m3)
Piso | Pavimento Térreo | 35.7588 (kgCO₂) | 446.985 | 1.9866 | 148.995 | 0.09933
Piso | Pavimento Térreo | 87.5196 (kgCO₂) | 1094 | 4.8622 | 364.665 | 0.24311
Piso | Pavimento Térreo | 228.205 (kgCO₂) | 2852.57 | 12.6781 | 950.855 | 0.633903
Piso | Pavimento Térreo | 136.422 (kgCO₂) | 1705.27 | 7.579 | 568.425 | 0.37895
Piso | Pavimento Térreo | 225.698 (kgCO₂) | 2821.23 | 12.5388 | 940.41 | 0.62694
Piso | Pavimento Térreo | 124.035 (kgCO₂) | 1550.44 | 6.89129 | 516.813 | 0.344542
Piso | Pavimento Térreo | 140.39 (kgCO₂) | 1754.88 | 7.79947 | 584.96 | 0.389974
Piso | Pavimento Térreo | 165.509 (kgCO₂) | 2068.86 | 9.19493 | 689.62 | 0.459746
Piso | Pavimento Térreo | 104.76 (kgCO₂) | 1309.5 | 5.82 | 436.5 | 0.291
Piso | Pavimento Intermediário | 26.784 (kgCO₂) | 334.8 | 1.488 | 111.6 | 0.0744
Piso | Pavimento Intermediário | 86.76 (kgCO₂) | 1084.5 | 4.82 | 361.5 | 0.241
Piso | Pavimento Intermediário | 188.381 (kgCO₂) | 2354.76 | 10.4656 | 784.92 | 0.52328
Piso | Primeiro Pavimento | 200.47 (kgCO₂) | 2505.87 | 11.1372 | 835.29 | 0.55686
2 x Piso | Primeiro Pavimento | 217.763 (kgCO₂) | 2722.04 | 12.0979 | 907.346 | 0.604897
Piso | Primeiro Pavimento | 324.459 (kgCO₂) | 4055.74 | 18.0258 | 1351.91 | 0.901276
Piso | Primeiro Pavimento | 107.741 (kgCO₂) | 1346.76 | 5.9856 | 448.92 | 0.29928
Piso | Primeiro Pavimento | 245.74 (kgCO₂) | 3071.75 | 13.6527 | 1023.92 | 0.682612
Piso | Primeiro Pavimento | 74.6316 (kgCO₂) | 932.895 | 4.1462 | 310.965 | 0.20731

# IfcDoor: Porta 23 (2)
In: Primeiro Pavimento
Type - OperationType: SINGLE_SWING_LEFT; ParameterTakesPrecedence: no; Sizeable: no
Type - Door Lining Properties - LiningThickness: 35 mm; LiningOffset: 0 mm
Type - Door Panel Properties - Panel 1 - PanelDepth: 30 mm; PanelOperation: SWINGING; PanelWidth: 1; PanelPosition: MIDDLE
OverallHeight: 2100 mm; Classification: EF_25_30 Doors and windows (Uniclass 2015); 3E 20 02 02 04 Porta de girar (NBR 15965-5); Porta (Classificação ARCHICAD)
Pset_DoorCommon - ThermalTransmittance: 0; IsExternal: no
AC_Pset_RenovationAndPhasing - Renovation Status: Existing
BaseQuantities - Height: 2100 mm; Depth: 140 mm
Name | OverallWidth (mm) = Width (mm) | Perimeter (mm) | Area (m2) | Volume (m3) = NetVolume (m3) = Component 1, Volume da Camada/ Componente (m3)
P10 | 870 | 5940 | 1.827 | 0.0741103
P13 | 670 | 5540 | 1.407 | 0.0607403 | Description: Porta-interior-generico-generico-generico-67cm

# IfcDoor: Porta 23 (2)
In: Pavimento Térreo
Type - OperationType: SINGLE_SWING_LEFT; ParameterTakesPrecedence: no; Sizeable: no
Type - Door Lining Properties - LiningThickness: 35 mm; LiningOffset: 140 mm
Type - Door Panel Properties - Panel 1 - PanelDepth: 30 mm; PanelOperation: SWINGING; PanelWidth: 1; PanelPosition: MIDDLE
OverallHeight: 2100 mm; OverallWidth: 770 mm; Classification: EF_25_30 Doors and windows (Uniclass 2015); 3E 20 02 02 04 Porta de girar (NBR 15965-5); Porta (Classificação ARCHICAD)
Pset_DoorCommon - ThermalTransmittance: 0
AC_Pset_RenovationAndPhasing - Renovation Status: Existing
BaseQuantities - Height: 2100 mm; Width: 770 mm; Perimeter: 5740 mm; Area: 1.617 m2; Volume: 0.0674253 m3; Depth: 140 mm; NetVolume: 0.0674253 m3
Component Quantities - Component 1, Volume da Camada/ Componente: 0.0674253 m3
Name | IsExternal
P03 | yes
P02 | no

# IfcDoor: Porta 23 (5)
Type - OperationType: SINGLE_SWING_RIGHT; ParameterTakesPrecedence: no; Sizeable: no
Type - Door Lining Properties - LiningThickness: 35 mm; LiningOffset: 0 mm
Type - Door Panel Properties - Panel 1 - PanelDepth: 30 mm; PanelOperation: SWINGING; PanelWidth: 1; PanelPosition: MIDDLE
OverallHeight: 2100 mm; Classification: EF_25_30 Doors and windows (Uniclass 2015); 3E 20 02 02 04 Porta de girar (NBR 15965-5); Porta (Classificação ARCHICAD)
Pset_DoorCommon - ThermalTransmittance: 0; IsExternal: no
AC_Pset_RenovationAndPhasing - Renovation Status: Existing
BaseQuantities - Height: 2100 mm; Depth: 140 mm
Name | In | OverallWidth (mm) = Width (mm) | Perimeter (mm) | Area (m2) | Volume (m3) = NetVolume (m3)
P05 | Pavimento Térreo | 870 | 5940 | 1.827 | 0.0741103 | Component Quantities - Component 1, Volume da Camada/ Componente: 0.0741103 m3
P04 | Primeiro Pavimento | 870 | 5940 | 1.827 | 0.0741103
P08 | Primeiro Pavimento | 870 | 5940 | 1.827 | 0.0741103
P07 | Primeiro Pavimento | 870 | 5940 | 1.827 | 0.0741103
P15 | Primeiro Pavimento | 670 | 5540 | 1.407 | 0.0607403 | Description: Porta-interior-generico-generico-generico-67cm

# IfcDoor: Porta 23, P11
In: Pavimento Térreo
Type - OperationType: SINGLE_SWING_RIGHT; ParameterTakesPrecedence: no; Sizeable: no
Type - Door Lining Properties - LiningThickness: 35 mm; LiningOffset: 140 mm
Type - Door Panel Properties - Panel 1 - PanelDepth: 30 mm; PanelOperation: SWINGING; PanelWidth: 1; PanelPosition: MIDDLE
Description: Porta-interior-generico-generico-generico-67cm; OverallHeight: 2100 mm; OverallWidth: 670 mm; Classification: EF_25_30 Doors and windows (Uniclass 2015); 3E 20 02 02 04 Porta de girar (NBR 15965-5); Porta (Classificação ARCHICAD)
Pset_DoorCommon - ThermalTransmittance: 0; IsExternal: no
AC_Pset_RenovationAndPhasing - Renovation Status: Existing
BaseQuantities - Height: 2050 mm; Width: 670 mm; Perimeter: 5440 mm; Area: 1.3735 m2; Volume: 0.0607403 m3; Depth: 140 mm; NetVolume: 0.0607403 m3
Component Quantities - Component 1, Volume da Camada/ Componente: 0.0607403 m3

# IfcDoor: Porta 23, P06
In: Pavimento Térreo
Type - OperationType: SINGLE_SWING_RIGHT; ParameterTakesPrecedence: no; Sizeable: no
Type - Door Lining Properties - LiningThickness: 35 mm; LiningOffset: 280 mm
Type - Door Panel Properties - Panel 1 - PanelDepth: 30 mm; PanelOperation: SWINGING; PanelWidth: 1; PanelPosition: MIDDLE
OverallHeight: 2100 mm; OverallWidth: 970 mm; Classification: EF_25_30 Doors and windows (Uniclass 2015); 3E 20 02 02 04 Porta de girar (NBR 15965-5); Porta (Classificação ARCHICAD)
Pset_DoorCommon - ThermalTransmittance: 0; IsExternal: yes
AC_Pset_RenovationAndPhasing - Renovation Status: Existing
BaseQuantities - Height: 2100 mm; Width: 970 mm; Perimeter: 6140 mm; Area: 2.037 m2; Volume: 0.105785 m3; Depth: 280 mm; NetVolume: 0.105785 m3
Component Quantities - Component 1, Volume da Camada/ Componente: 0.105785 m3

# IfcDoor: Porta de Correr com Travessa 23, P09
In: Pavimento Térreo
Type - OperationType: USERDEFINED; ParameterTakesPrecedence: no; Sizeable: no
OverallHeight: 2500 mm; OverallWidth: 5200 mm; Classification: EF_25_30 Doors and windows (Uniclass 2015); Porta (Classificação ARCHICAD); 3E 20 02 02 02 Porta de correr (NBR 15965-5)
Pset_DoorCommon - ThermalTransmittance: 0; GlazingAreaFraction: 10.123; IsExternal: yes
AC_Pset_RenovationAndPhasing - Renovation Status: Existing
BaseQuantities - Height: 2500 mm; Width: 5200 mm; Perimeter: 15400 mm; Area: 13 m2; Volume: 0.174996 m3; Depth: 140 mm; NetVolume: 0.174996 m3
Component Quantities - Component 1, Volume da Camada/ Componente: 0.174996 m3

# IfcFlowTerminal: Bancada 23 (2)
In: Pavimento Térreo
Type - PredefinedType: SINK
Description: bancada-cozinha-generico-generico-generico; Classification: EF_40_40 Equipment (Uniclass 2015); Terminal Hidrosanitário (Classificação ARCHICAD); 2C 78 06 06 Pia dupla (NBR 15965-4)
AC_Pset_RenovationAndPhasing - Renovation Status: Existing
Name | Component 1, Volume da Camada/ Componente (m3)
Bancada-cozinha | 0.052836
Bancada-cozinha | 0.0314178

# IfcFlowTerminal: Banheira 23, Banheira
In: Primeiro Pavimento
Type - PredefinedType: BATH
Description: banheira-retangular-generico-generico-ceramica-170cm-75cm; Classification: EF_40_40 Equipment (Uniclass 2015); Terminal Hidrosanitário (Classificação ARCHICAD); 2C 78 10 Banheiras (NBR 15965-4)
AC_Pset_RenovationAndPhasing - Renovation Status: Existing
Component Quantities - Component 1, Volume da Camada/ Componente: 0.0883261 m3

# IfcFlowTerminal: Bidê 23, Bidê
In: Primeiro Pavimento
Type - PredefinedType: BIDET
Description: bide--generico-generico-ceramica; Classification: EF_40_40 Equipment (Uniclass 2015); Terminal Hidrosanitário (Classificação ARCHICAD); 2C 78 26 Bidês (NBR 15965-4)
AC_Pset_RenovationAndPhasing - Renovation Status: Existing
Component Quantities - Component 1, Volume da Camada/ Componente: 0 m3

# IfcFlowTerminal: Lavatório 23 (3)
Type - PredefinedType: WASHHANDBASIN
Description: lavatório--generico-generico-ceramica; Classification: EF_40_40 Equipment (Uniclass 2015); Terminal Hidrosanitário (Classificação ARCHICAD); 2C 78 06 02 Pia individual (NBR 15965-4)
AC_Pset_RenovationAndPhasing - Renovation Status: Existing
Name | In
Lavatório | Pavimento Térreo | Component Quantities - Component 1, Volume da Camada/ Componente: 0.00448164 m3
2 x Lavatório | Primeiro Pavimento

# IfcFlowTerminal: Tanque de Lavar Roupa 23, Tanque
In: Pavimento Térreo
Type - PredefinedType: SINK
Description: tanque--generico-generico-generico; Classification: EF_40_40 Equipment (Uniclass 2015); Terminal Hidrosanitário (Classificação ARCHICAD); 2C 78 06 18 18 Pia de serviço (NBR 15965-4)
AC_Pset_RenovationAndPhasing - Renovation Status: Existing
Component Quantities - Component 1, Volume da Camada/ Componente: 0.0252197 m3

# IfcFlowTerminal: Vaso Sanitário 23 (3)
Type - PredefinedType: TOILETPAN
Description: vaso_sanitario-valvula-generico-generico-ceramica; Classification: EF_40_40 Equipment (Uniclass 2015); Terminal Hidrosanitário (Classificação ARCHICAD); 2C 78 18 10 Vasos sanitários sem caixa (NBR 15965-4)
AC_Pset_RenovationAndPhasing - Renovation Status: Existing
Name | In
Vaso Sanitário | Pavimento Térreo | Component Quantities - Component 1, Volume da Camada/ Componente: 0.00933915 m3
2 x Vaso Sanitário | Primeiro Pavimento

# IfcMember: IfcMember (66)
AC_Pset_RenovationAndPhasing - Renovation Status: Existing
Name | In | Classification | Material | Component 1, Carbono Incorporado | Component 1, Energia Incorporada (MJ) | GrossVolume (m3) = NetVolume (m3) = Component 1, Volume da Camada/ Componente (m3) | Component 1, Massa (kg)
Lance - 025 | Pavimento Térreo | Estrutura de Escada (Classificação ARCHICAD) | Concreto Armado - Estrutural | 282.547 (kgCO₂) | 2720.39 | 0.486479 | 1167.55
RISER-215 | Pavimento Térreo | Acabamento Espelho (Classificação ARCHICAD) | Concreto - Contra Piso | 0.838776 (kgCO₂) | 5.80088 | 0.00435501 | 7.83902
RISER-216 | Pavimento Térreo | Acabamento Espelho (Classificação ARCHICAD) | Concreto - Contra Piso | 0.838776 (kgCO₂) | 5.80088 | 0.00435501 | 7.83902
RISER-217 | Pavimento Térreo | Acabamento Espelho (Classificação ARCHICAD) | Concreto - Contra Piso | 0.838776 (kgCO₂) | 5.80088 | 0.00435501 | 7.83902
RISER-218 | Pavimento Térreo | Acabamento Espelho (Classificação ARCHICAD) | Concreto - Contra Piso | 0.838776 (kgCO₂) | 5.80088 | 0.00435501 | 7.83902
RISER-219 | Pavimento Térreo | Acabamento Espelho (Classificação ARCHICAD) | Concreto - Contra Piso | 0.838776 (kgCO₂) | 5.80088 | 0.00435501 | 7.83902
RISER-220 | Pavimento Térreo | Acabamento Espelho (Classificação ARCHICAD) | Concreto - Contra Piso | 0.838776 (kgCO₂) | 5.80088 | 0.00435501 | 7.83902
RISER-221 | Pavimento Térreo | Acabamento Espelho (Classificação ARCHICAD) | Concreto - Contra Piso | 0.838776 (kgCO₂) | 5.80088 | 0.00435501 | 7.83902
Piso Esc. - 184 | Pavimento Térreo | Acabamento Piso (Classificação ARCHICAD) | Concreto - Contra Piso | 1.79128 (kgCO₂) | 12.3883 | 0.00930052 | 16.7409
Piso Esc. - 185 | Pavimento Térreo | Acabamento Piso (Classificação ARCHICAD) | Concreto - Contra Piso | 1.79128 (kgCO₂) | 12.3883 | 0.00930052 | 16.7409
Piso Esc. - 186 | Pavimento Térreo | Acabamento Piso (Classificação ARCHICAD) | Concreto - Contra Piso | 1.79128 (kgCO₂) | 12.3883 | 0.00930052 | 16.7409
Piso Esc. - 187 | Pavimento Térreo | Acabamento Piso (Classificação ARCHICAD) | Concreto - Contra Piso | 1.79128 (kgCO₂) | 12.3883 | 0.00930052 | 16.7409
Piso Esc. - 188 | Pavimento Térreo | Acabamento Piso (Classificação ARCHICAD) | Concreto - Contra Piso | 1.79128 (kgCO₂) | 12.3883 | 0.00930052 | 16.7409
Piso Esc. - 189 | Pavimento Térreo | Acabamento Piso (Classificação ARCHICAD) | Concreto - Contra Piso | 1.79128 (kgCO₂) | 12.3883 | 0.00930052 | 16.7409
Piso Esc. - 190 | Pavimento Térreo | Acabamento Piso (Classificação ARCHICAD) | Concreto - Contra Piso | 1.79128 (kgCO₂) | 12.3883 | 0.00930052 | 16.7409
Lance - 022 | Pavimento Térreo | Estrutura de Escada (Classificação ARCHICAD) | Concreto Armado - Estrutural | 174.476 (kgCO₂) | 1679.87 | 0.300406 | 720.975
RISER-187 | Pavimento Térreo | Acabamento Espelho (Classificação ARCHICAD) | Concreto - Contra Piso | 0.572985 (kgCO₂) | 3.9627 | 0.002975 | 5.355
RISER-188 | Pavimento Térreo | Acabamento Espelho (Classificação ARCHICAD) | Concreto - Contra Piso | 0.572985 (kgCO₂) | 3.9627 | 0.002975 | 5.355
RISER-189 | Pavimento Térreo | Acabamento Espelho (Classificação ARCHICAD) | Concreto - Contra Piso | 0.572985 (kgCO₂) | 3.9627 | 0.002975 | 5.355
RISER-190 | Pavimento Térreo | Acabamento Espelho (Classificação ARCHICAD) | Concreto - Contra Piso | 0.572985 (kgCO₂) | 3.9627 | 0.002975 | 5.355
RISER-191 | Pavimento Térreo | Acabamento Espelho (Classificação ARCHICAD) | Concreto - Contra Piso | 0.572985 (kgCO₂) | 3.9627 | 0.002975 | 5.355
RISER-192 | Pavimento Térreo | Acabamento Espelho (Classificação ARCHICAD) | Concreto - Contra Piso | 0.572985 (kgCO₂) | 3.9627 | 0.002975 | 5.355
RISER-193 | Pavimento Térreo | Acabamento Espelho (Classificação ARCHICAD) | Concreto - Contra Piso | 0.572985 (kgCO₂) | 3.9627 | 0.002975 | 5.355
RISER-194 | Pavimento Térreo | Acabamento Espelho (Classificação ARCHICAD) | Concreto - Contra Piso | 0.650025 (kgCO₂) | 4.4955 | 0.003375 | 6.075
Piso Esc. - 156 | Pavimento Térreo | Acabamento Piso (Classificação ARCHICAD) | Concreto - Contra Piso | 1.1572 (kgCO₂) | 8.00308 | 0.00600832 | 10.815
Piso Esc. - 157 | Pavimento Térreo | Acabamento Piso (Classificação ARCHICAD) | Concreto - Contra Piso | 1.1572 (kgCO₂) | 8.00308 | 0.00600832 | 10.815
Piso Esc. - 158 | Pavimento Térreo | Acabamento Piso (Classificação ARCHICAD) | Concreto - Contra Piso | 1.1572 (kgCO₂) | 8.00308 | 0.00600832 | 10.815
Piso Esc. - 159 | Pavimento Térreo | Acabamento Piso (Classificação ARCHICAD) | Concreto - Contra Piso | 1.1572 (kgCO₂) | 8.00308 | 0.00600832 | 10.815
Piso Esc. - 160 | Pavimento Térreo | Acabamento Piso (Classificação ARCHICAD) | Concreto - Contra Piso | 1.1572 (kgCO₂) | 8.00308 | 0.00600832 | 10.815
Piso Esc. - 161 | Pavimento Térreo | Acabamento Piso (Classificação ARCHICAD) | Concreto - Contra Piso | 1.1572 (kgCO₂) | 8.00308 | 0.00600832 | 10.815
Piso Esc. - 162 | Pavimento Térreo | Acabamento Piso (Classificação ARCHICAD) | Concreto - Contra Piso | 1.1572 (kgCO₂) | 8.00308 | 0.00600832 | 10.815
Lance - 022 | Pavimento Térreo | Estrutura de Escada (Classificação ARCHICAD) | Concreto Armado - Estrutural | 175.128 (kgCO₂) | 1686.15 | 0.301529 | 723.67
RISER-195 | Pavimento Térreo | Acabamento Espelho (Classificação ARCHICAD) | Concreto - Contra Piso | 0.572985 (kgCO₂) | 3.9627 | 0.002975 | 5.355
RISER-196 | Pavimento Térreo | Acabamento Espelho (Classificação ARCHICAD) | Concreto - Contra Piso | 0.572985 (kgCO₂) | 3.9627 | 0.002975 | 5.355
RISER-197 | Pavimento Térreo | Acabamento Espelho (Classificação ARCHICAD) | Concreto - Contra Piso | 0.572985 (kgCO₂) | 3.9627 | 0.002975 | 5.355
RISER-198 | Pavimento Térreo | Acabamento Espelho (Classificação ARCHICAD) | Concreto - Contra Piso | 0.572985 (kgCO₂) | 3.9627 | 0.002975 | 5.355
RISER-199 | Pavimento Térreo | Acabamento Espelho (Classificação ARCHICAD) | Concreto - Contra Piso | 0.572985 (kgCO₂) | 3.9627 | 0.002975 | 5.355
RISER-200 | Pavimento Térreo | Acabamento Espelho (Classificação ARCHICAD) | Concreto - Contra Piso | 0.572985 (kgCO₂) | 3.9627 | 0.002975 | 5.355
RISER-201 | Pavimento Térreo | Acabamento Espelho (Classificação ARCHICAD) | Concreto - Contra Piso | 0.572985 (kgCO₂) | 3.9627 | 0.002975 | 5.355
RISER-202 | Pavimento Térreo | Acabamento Espelho (Classificação ARCHICAD) | Concreto - Contra Piso | 0.650025 (kgCO₂) | 4.4955 | 0.003375 | 6.075
Piso Esc. - 163 | Pavimento Térreo | Acabamento Piso (Classificação ARCHICAD) | Concreto - Contra Piso | 1.16338 (kgCO₂) | 8.04581 | 0.0060404 | 10.8727
Piso Esc. - 164 | Pavimento Térreo | Acabamento Piso (Classificação ARCHICAD) | Concreto - Contra Piso | 1.16338 (kgCO₂) | 8.04581 | 0.0060404 | 10.8727
Piso Esc. - 165 | Pavimento Térreo | Acabamento Piso (Classificação ARCHICAD) | Concreto - Contra Piso | 1.16338 (kgCO₂) | 8.04581 | 0.0060404 | 10.8727
Piso Esc. - 166 | Pavimento Térreo | Acabamento Piso (Classificação ARCHICAD) | Concreto - Contra Piso | 1.16338 (kgCO₂) | 8.04581 | 0.0060404 | 10.8727
Piso Esc. - 167 | Pavimento Térreo | Acabamento Piso (Classificação ARCHICAD) | Concreto - Contra Piso | 1.16338 (kgCO₂) | 8.04581 | 0.0060404 | 10.8727
Piso Esc. - 168 | Pavimento Térreo | Acabamento Piso (Classificação ARCHICAD) | Concreto - Contra Piso | 1.16338 (kgCO₂) | 8.04581 | 0.0060404 | 10.8727
Piso Esc. - 169 | Pavimento Térreo | Acabamento Piso (Classificação ARCHICAD) | Concreto - Contra Piso | 1.16338 (kgCO₂) | 8.04581 | 0.0060404 | 10.8727
Lance - 026 | Pavimento Intermediário | Estrutura de Escada (Classificação ARCHICAD) | Concreto Armado - Estrutural | 236.775 (kgCO₂) | 2279.69 | 0.40767 | 978.409
RISER-227 | Pavimento Intermediário | Acabamento Espelho (Classificação ARCHICAD) | Concreto - Contra Piso | 0.545013 (kgCO₂) | 3.76925 | 0.00282977 | 5.09358
RISER-228 | Pavimento Intermediário | Acabamento Espelho (Classificação ARCHICAD) | Concreto - Contra Piso | 0.545013 (kgCO₂) | 3.76925 | 0.00282977 | 5.09358
RISER-229 | Pavimento Intermediário | Acabamento Espelho (Classificação ARCHICAD) | Concreto - Contra Piso | 0.545013 (kgCO₂) | 3.76925 | 0.00282977 | 5.09358
RISER-230 | Pavimento Intermediário | Acabamento Espelho (Classificação ARCHICAD) | Concreto - Contra Piso | 0.545013 (kgCO₂) | 3.76925 | 0.00282977 | 5.09358
RISER-231 | Pavimento Intermediário | Acabamento Espelho (Classificação ARCHICAD) | Concreto - Contra Piso | 0.545013 (kgCO₂) | 3.76925 | 0.00282977 | 5.09358
RISER-232 | Pavimento Intermediário | Acabamento Espelho (Classificação ARCHICAD) | Concreto - Contra Piso | 0.545013 (kgCO₂) | 3.76925 | 0.00282977 | 5.09358
RISER-233 | Pavimento Intermediário | Acabamento Espelho (Classificação ARCHICAD) | Concreto - Contra Piso | 0.545013 (kgCO₂) | 3.76925 | 0.00282977 | 5.09358
RISER-234 | Pavimento Intermediário | Acabamento Espelho (Classificação ARCHICAD) | Concreto - Contra Piso | 0.545013 (kgCO₂) | 3.76925 | 0.00282977 | 5.09358
RISER-235 | Pavimento Intermediário | Acabamento Espelho (Classificação ARCHICAD) | Concreto - Contra Piso | 0.545013 (kgCO₂) | 3.76925 | 0.00282977 | 5.09358
Piso Esc. - 196 | Pavimento Intermediário | Acabamento Piso (Classificação ARCHICAD) | Concreto - Contra Piso | 1.19233 (kgCO₂) | 8.24604 | 0.00619072 | 11.1433
Piso Esc. - 197 | Pavimento Intermediário | Acabamento Piso (Classificação ARCHICAD) | Concreto - Contra Piso | 1.19233 (kgCO₂) | 8.24604 | 0.00619072 | 11.1433
Piso Esc. - 198 | Pavimento Intermediário | Acabamento Piso (Classificação ARCHICAD) | Concreto - Contra Piso | 1.19233 (kgCO₂) | 8.24604 | 0.00619072 | 11.1433
Piso Esc. - 199 | Pavimento Intermediário | Acabamento Piso (Classificação ARCHICAD) | Concreto - Contra Piso | 1.19233 (kgCO₂) | 8.24604 | 0.00619072 | 11.1433
Piso Esc. - 200 | Pavimento Intermediário | Acabamento Piso (Classificação ARCHICAD) | Concreto - Contra Piso | 1.19233 (kgCO₂) | 8.24604 | 0.00619072 | 11.1433
Piso Esc. - 201 | Pavimento Intermediário | Acabamento Piso (Classificação ARCHICAD) | Concreto - Contra Piso | 1.19233 (kgCO₂) | 8.24604 | 0.00619072 | 11.1433
Piso Esc. - 202 | Pavimento Intermediário | Acabamento Piso (Classificação ARCHICAD) | Concreto - Contra Piso | 1.19233 (kgCO₂) | 8.24604 | 0.00619072 | 11.1433
Piso Esc. - 203 | Pavimento Intermediário | Acabamento Piso (Classificação ARCHICAD) | Concreto - Contra Piso | 1.19233 (kgCO₂) | 8.24604 | 0.00619072 | 11.1433
Piso Esc. - 204 | Pavimento Intermediário | Acabamento Piso (Classificação ARCHICAD) | Concreto - Contra Piso | 1.00237 (kgCO₂) | 6.93228 | 0.00520441 | 9.36794

# IfcOpeningElement (39)
Name | In | Depth (mm) | Height (mm) | Width (mm) | Area (m2) | Volume (m3)
3 x J04 | Pavimento Térreo | 140 | 400 | 975 | 0.39 | 0.004921
2 x J05 | Pavimento Térreo | 140 | 400 | 650 | 0.26 | 0.003556
P03 | Pavimento Térreo | 140 | 2100 | 770 | 1.617 | 0.0674253
P06 | Pavimento Térreo | 280 | 2100 | 970 | 2.037 | 0.105785
8 x J02 | Pavimento Térreo | 140 | 0 | 0 | 0 | 0.01799
P06 | Pavimento Térreo | 140 | 2500 | 5200 | 13 | 0.174996
2 x J06 | Pavimento Térreo | 280 | 700 | 1000 | 0.7 | 0.00896
P02 | Pavimento Térreo | 140 | 2100 | 770 | 1.617 | 0.0674253
Vão | Pavimento Térreo | 100 | 2500 | 700 | 1.75 | 0
P01 | Pavimento Térreo | 140 | 2050 | 670 | 1.3735 | 0.0607403
P05 | Pavimento Térreo | 140 | 2100 | 870 | 1.827 | 0.0741103
Vão | Pavimento Térreo | 280 | 1250 | 1000 | 1.25 | 0
J03 | Pavimento Térreo | 140 | 900 | 2200 | 1.98 | 0.01351
3 x J04 | Pavimento Térreo | 140 | 0 | 0 | 0 | 0.004606
P04 | Primeiro Pavimento | 140 | 2100 | 870 | 1.827 | 0.0741103
P06 | Primeiro Pavimento | 140 | 2100 | 870 | 1.827 | 0.0741103
P08 | Primeiro Pavimento | 140 | 2100 | 870 | 1.827 | 0.0741103
2 x J07 | Primeiro Pavimento | 100 | 740 | 740 | 0.5476 | 0.0098975
4 x J02 | Primeiro Pavimento | 140 | 1200 | 2850 | 3.42 | 0.096691
P07 | Primeiro Pavimento | 140 | 2100 | 870 | 1.827 | 0.0741103
P12 | Primeiro Pavimento | 140 | 2100 | 670 | 1.407 | 0.0607403
P14 | Primeiro Pavimento | 140 | 2100 | 670 | 1.407 | 0.0607403

# IfcRoof (5)
In: Pavimento Cobertura
Pset_ManufacturerTypeInformation - ProductionYear: DD/MM/YYYY
AC_Pset_RenovationAndPhasing - Renovation Status: Existing
Component Properties - Component 1, Tipo de Componente: Nenhum
Name | Classification | Material | TotalArea (m2) = TotalSurfaceArea (m2) | Component 1, Carbono Incorporado | Component 1, Energia Incorporada (MJ) | Component 1, Massa (kg) | Component 1, Área Projetada Componente/Camada (m2) | Component 1, Espessura da Camada (mm) | Component 1, Volume da Camada/ Componente (m3) | Description | IsExternal
Esboço | Cobertura (Classificação ARCHICAD) | GENÉRICO - COBERTURA | 163.027 | 782.529 (kgCO₂) | 9781.61 | 3260.54 | 163.095 | 10 | 1.63027
Laje de cobertura | Cobertura (Classificação ARCHICAD); EF_30_10 Roofs (Uniclass 2015); 3E 12 06 08 Laje (NBR 15965-5) | Concreto Armado - Estrutural | 111.751 | 3441.26 (kgCO₂) | 33132.8 | 14220.1 | 125.432 | 50 | 5.92503 | Laje-cobertura-generico-in_loco-concreto_armado-50mm | no
Laje de cobertura | Cobertura (Classificação ARCHICAD); EF_30_10 Roofs (Uniclass 2015); 3E 12 06 08 Laje (NBR 15965-5) | Concreto Armado - Estrutural | 14.2104 | 445.33 (kgCO₂) | 4287.68 | 1840.21 | 15.686 | 51.5307 | 0.766752 | Laje-cobertura-generico-in_loco-concreto_armado-50mm | no
Laje de cobertura | Cobertura (Classificação ARCHICAD); EF_30_10 Roofs (Uniclass 2015); 3E 12 06 08 Laje (NBR 15965-5) | Concreto Armado - Estrutural | 14.2846 | 447.725 (kgCO₂) | 4310.74 | 1850.1 | 15.686 | 51.5307 | 0.770877 | Laje-cobertura-generico-in_loco-concreto_armado-50mm | no
Telhado | Cobertura (Classificação ARCHICAD); EF_30_10 Roofs (Uniclass 2015); 3E 14 04 02 10 Telhamento (NBR 15965-5) | Telha - Cobertura | 160.215 | 3845.17 (kgCO₂) | 48064.6 | 16021.5 | 160.555 | 50 | 8.01077 | cobertura-telhas-generico-generico-ceramica-50mm | yes

# IfcSlab: Concreto Armado - Estrutural 100 (4)
Type - PredefinedType: FLOOR
Classification: EF_30_20 Floors (Uniclass 2015); 3E 12 06 08 Laje (NBR 15965-5); Laje (Classificação ARCHICAD); Material: Concreto Armado - Estrutural 100 mm
AC_Pset_RenovationAndPhasing - Renovation Status: Existing
Pset_SlabCommon - LoadBearing: yes
Component Properties - Component 1, Tipo de Componente: Nenhum
BaseQuantities - Width: 100 mm
Component Quantities - Component 1, Espessura da Camada: 100 mm
Name | In | Description | IsExternal | Component 1, Carbono Incorporado | Component 1, Energia Incorporada (MJ) | Perimeter (mm) | GrossArea (m2) = NetArea (m2) = Component 1, Área Projetada Componente/Camada (m2) | GrossVolume (m3) = NetVolume (m3) = Component 1, Volume da Camada/ Componente (m3) | Component 1, Massa (kg)
Laje-03 | Pavimento Térreo | Laje-exterior-generico-in_loco-concreto_armado-100mm | yes | 1643.95 (kgCO₂) | 15828.2 | 21300 | 28.305 | 2.8305 | 6793.2
Laje-04 | Pavimento Térreo | Laje-interior-generico-in_loco-concreto_armado-100m | no | 4605.75 (kgCO₂) | 44344.6 | 35700 | 79.38 | 7.93001 | 19032
Laje-05 | Pavimento Intermediário | Laje-interior-concreto_armado-100mm | no | 1153.21 (kgCO₂) | 11103.2 | 18000 | 19.8555 | 1.98555 | 4765.32
Laje-01 | Primeiro Pavimento | Laje-interior-generico-in_loco-concreto_armado-100mm | no | 4940.27 (kgCO₂) | 47565.4 | 40740 | 85.0652 | 8.50597 | 20414.3

# IfcSlab: IfcSlab (2)
Type - PredefinedType: LANDING
Classification: 3E 08 06 04 Escada (NBR 15965-5); Patamar de Escada (Classificação ARCHICAD); Material: Concreto Armado - Estrutural
AC_Pset_RenovationAndPhasing - Renovation Status: Existing
Name | In | Component 1, Carbono Incorporado | Component 1, Energia Incorporada (MJ) | GrossVolume (m3) = NetVolume (m3) = Component 1, Volume da Camada/ Componente (m3) | Component 1, Massa (kg)
Patamar - 010 | Pavimento Térreo | 92.3302 (kgCO₂) | 888.964 | 0.158971 | 381.53
Patamar - 011 | Pavimento Intermediário | 63.3072 (kgCO₂) | 609.528 | 0.109 | 261.6

# IfcStair (4)
Classification: EF_35_10 Stairs (Uniclass 2015); 3E 08 06 04 Escada (NBR 15965-5); Escada (Classificação ARCHICAD)
Pset_StairCommon - RequiredHeadroom: 2200 mm
AC_Pset_RenovationAndPhasing - Renovation Status: Existing
Name | In | Description | NumberOfRiser | NumberOfTreads | RiserHeight (mm) | IsExternal | Length (mm) | Height (mm) | GrossVolume (m3) = NetVolume (m3)
Escada | Pavimento Térreo | Escada-interior-generico-in_loco-concreto_armado | 8 | 8 | 162.5 | no | 2910 | 1300 | 0.778093
Escada | Pavimento Térreo | Escada-exterior-generico-in_loco-concreto_armado | 8 | 7 | 168.75 | yes | 1962.91 | 1350 | 0.366664
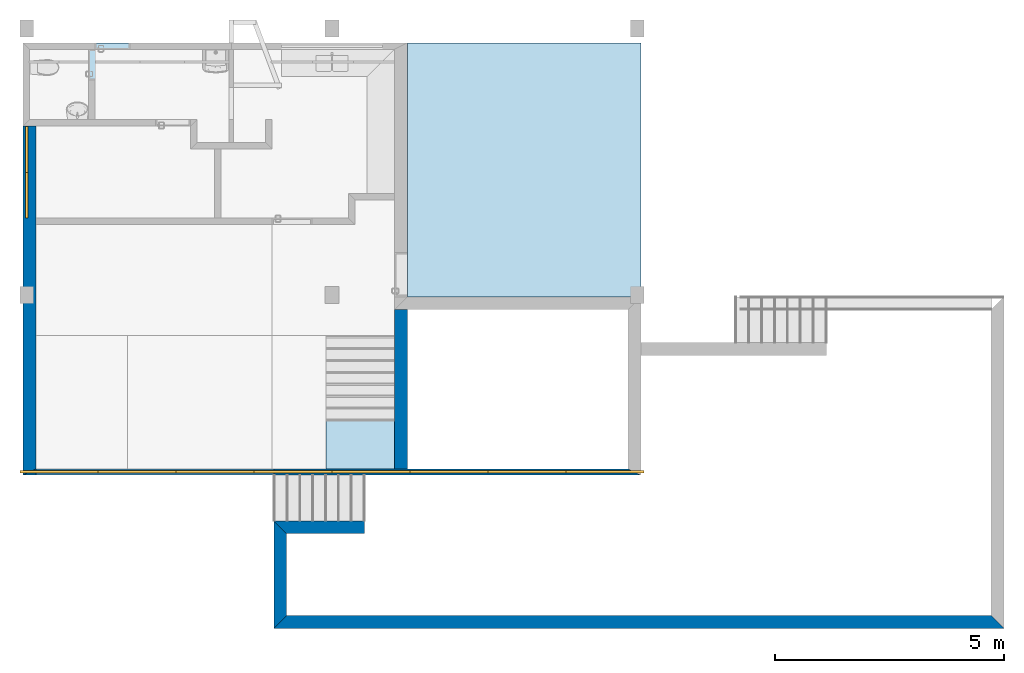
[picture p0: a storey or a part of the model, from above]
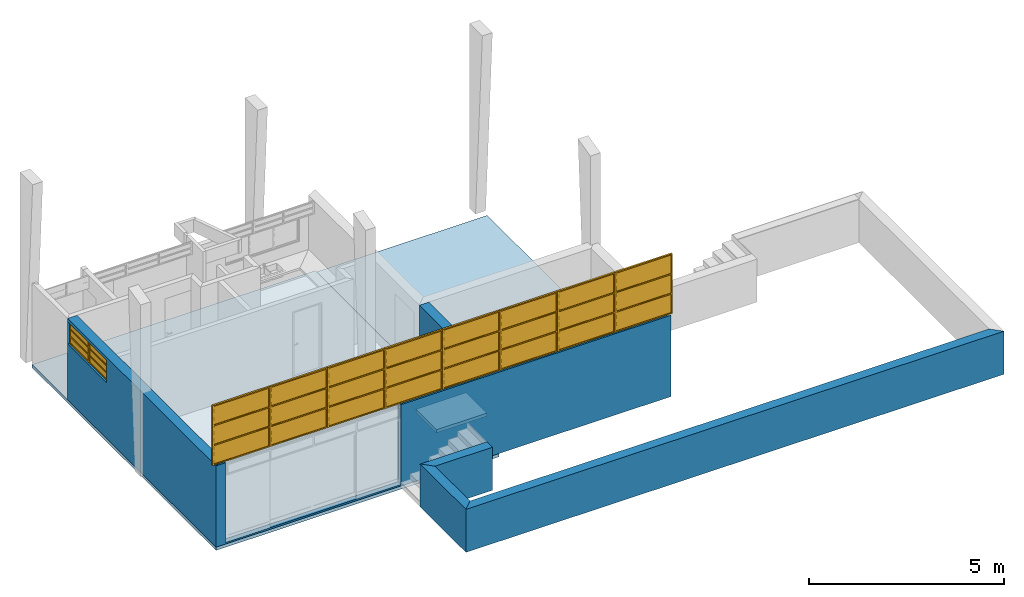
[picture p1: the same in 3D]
Properties of the parts of a building model (IFC2X3), part 2 of 2

# IfcStair (4)
Name | In | Description | NumberOfRiser | NumberOfTreads | RiserHeight (mm) | IsExternal | Length (mm) | Height (mm) | GrossVolume (m3) = NetVolume (m3)
Escada | Pavimento Térreo | Escada-exterior-generico-in_loco-concreto_armado | 8 | 7 | 168.75 | yes | 1974.14 | 1350 | 0.368012
Escada | Pavimento Intermediário | Escada-interior-generico-in_loco-concreto_armado | 9 | 10 | 158.889 | no | 3431.98 | 1430 | 0.619655

# IfcWall: Alvenaria Tijolo Maciço com Revestimento 10cm 100 (2)
In: Primeiro Pavimento
Description: Parede-interior-generico-in_loco-tijolo_maciço-100mm; Classification: EF_25_10 Walls (Uniclass 2015); Parede (Classificação ARCHICAD); 3E 14 02 00 Parede (NBR 15965-5)
Pset_WallCommon - AcousticRating: 0.00; LoadBearing: yes; IsExternal: no
AC_Pset_RenovationAndPhasing - Renovation Status: Existing
BaseQuantities - Width: 100 mm
Name | Length (mm) | Height (mm) | GrossFootprintArea (m2) = NetFootprintArea (m2) | GrossSideArea (m2) = NetSideArea (m2) | GrossVolume (m3) = NetVolume (m3)
Parede | 1000 | 2940.8 | 0.1012 | 2.81115 | 0.284641
Parede | 480 | 2519.44 | 0.0446 | 1.15615 | 0.109864

# IfcWall: Alvenaria Tijolo Maciço com Revestimento 14cm 140 (19)
In: Primeiro Pavimento
Pset_WallCommon - AcousticRating: 0.00; LoadBearing: yes
AC_Pset_RenovationAndPhasing - Renovation Status: Existing
BaseQuantities - Width: 140 mm
Name | Description | Classification | IsExternal | Length (mm) | Height (mm) | GrossFootprintArea (m2) = NetFootprintArea (m2) | GrossSideArea (m2) | NetSideArea (m2) | GrossVolume (m3) | NetVolume (m3)
Parede | Parede-interior-generico-in_loco-tijolo_maciço-140mm | EF_25_10 Walls (Uniclass 2015); Parede (Classificação ARCHICAD); 3E 14 02 00 Parede (NBR 15965-5) | no | 7560 | 2771.39 | 1.0584 | 20.5426 | 15.0616 | 2.91471 | 2.14737
Parede | Parede-exterior-generico-in_loco-tijolo_maciço-140mm | EF_25_10 Walls (Uniclass 2015); 3E 14 02 00 Parede (NBR 15965-5); Parede (Classificação ARCHICAD) | yes | 13640 | 2749.99 | 1.78295 | 34.6668 | 21.0108 | 4.88865 | 2.97681
Parede | Parede-interior-generico-in_loco-tijolo_maciço-140mm | EF_25_10 Walls (Uniclass 2015); Parede (Classificação ARCHICAD); 3E 14 02 00 Parede (NBR 15965-5) | no | 2740 | 3020.72 | 0.389 | 8.17196 | 8.17196 | 1.16478 | 1.16478
Parede | Parede-interior-generico-in_loco-tijolo_maciço-140mm | EF_25_10 Walls (Uniclass 2015); Parede (Classificação ARCHICAD); 3E 14 02 00 Parede (NBR 15965-5) | no | 3790 | 3211.87 | 0.5346 | 11.2772 | 11.2772 | 1.58984 | 1.58984
Parede | Parede-interior-generico-in_loco-tijolo_maciço-140mm | EF_25_10 Walls (Uniclass 2015); Parede (Classificação ARCHICAD); 3E 14 02 00 Parede (NBR 15965-5) | no | 5890 | 3211.87 | 0.828 | 16.3193 | 14.4923 | 2.32421 | 2.06843
Parede | Parede-interior-generico-in_loco-tijolo_maciço-140mm | EF_25_10 Walls (Uniclass 2015); Parede (Classificação ARCHICAD); 3E 14 02 00 Parede (NBR 15965-5) | no | 1895 | 3197.33 | 0.2727 | 5.6141 | 5.6141 | 0.804178 | 0.804178
Parede | Parede-interior-generico-in_loco-tijolo_maciço-140mm | EF_25_10 Walls (Uniclass 2015); Parede (Classificação ARCHICAD); 3E 14 02 00 Parede (NBR 15965-5) | no | 3750 | 2108.18 | 0.5304 | 7.86008 | 7.86008 | 1.10889 | 1.10889
Parede | Parede-interior-generico-in_loco-tijolo_maciço-140mm | EF_25_10 Walls (Uniclass 2015); Parede (Classificação ARCHICAD); 3E 14 02 00 Parede (NBR 15965-5) | no | 3130 | 2265.26 | 0.4382 | 7.03353 | 7.03353 | 0.984915 | 0.984915
Parede | Parede-interior-generico-in_loco-tijolo_maciço-140mm | EF_25_10 Walls (Uniclass 2015); Parede (Classificação ARCHICAD); 3E 14 02 00 Parede (NBR 15965-5) | no | 1895 | 3211.87 | 0.2727 | 5.72669 | 5.72669 | 0.820009 | 0.820009
Parede | Parede-interior-generico-in_loco-tijolo_maciço-140mm | EF_25_10 Walls (Uniclass 2015); Parede (Classificação ARCHICAD); 3E 14 02 00 Parede (NBR 15965-5) | no | 700 | 3197.33 | 0.0872 | 2.16232 | 2.16232 | 0.277285 | 0.277285
Parede | Parede-interior-generico-in_loco-tijolo_maciço-140mm | EF_25_10 Walls (Uniclass 2015); Parede (Classificação ARCHICAD); 3E 14 02 00 Parede (NBR 15965-5) | no | 880 | 2467.21 | 0.1286 | 2.09662 | 2.09662 | 0.302533 | 0.302533
Parede | Parede-interior-generico-in_loco-tijolo_maciço-140mm | EF_25_10 Walls (Uniclass 2015); Parede (Classificação ARCHICAD); 3E 14 02 00 Parede (NBR 15965-5) | no | 3330 | 2265.26 | 0.4628 | 7.46166 | 7.46166 | 1.04025 | 1.04025
Parede | Parede-interior-generico-in_loco-tijolo_maciço-140mm | EF_25_10 Walls (Uniclass 2015); Parede (Classificação ARCHICAD); 3E 14 02 00 Parede (NBR 15965-5) | no | 880 | 2467.21 | 0.0500328 | 0.734262 | 0.734262 | 0.0938204 | 0.0938204
Parede | Parede-interior-generico-in_loco-tijolo_maciço-140mm | EF_25_10 Walls (Uniclass 2015); Parede (Classificação ARCHICAD); 3E 14 02 00 Parede (NBR 15965-5) | no | 1440 | 2467.21 | 0.2016 | 3.27274 | 3.27274 | 0.45962 | 0.45962
Parede | Parede-interior-generico-in_loco-tijolo_maciço-140mm | EF_25_10 Walls (Uniclass 2015); Parede (Classificação ARCHICAD); 3E 14 02 00 Parede (NBR 15965-5) | no | 1800 | 2467.21 | 0.1558 | 4.16694 | 2.75994 | 0.602833 | 0.405853
Parede | Parede-interior-generico-in_loco-tijolo_maciço-140mm | EF_25_10 Walls (Uniclass 2015); Parede (Classificação ARCHICAD); 3E 14 02 00 Parede (NBR 15965-5) | no | 2150 | 3015.73 | 0.2018 | 5.7135 | 4.3065 | 0.806561 | 0.609581
Parede | Parede-interior-generico-in_loco-tijolo_maciço-140mm | EF_25_10 Walls (Uniclass 2015); Parede (Classificação ARCHICAD); 3E 14 02 00 Parede (NBR 15965-5) | no | 1670 | 2399.89 | 0.2392 | 4.00145 | 4.00145 | 0.569844 | 0.569844
Parede | Parede-interior-generico-in_loco-tijolo_maciço-140mm | EF_25_10 Walls (Uniclass 2015); Parede (Classificação ARCHICAD); 3E 14 02 00 Parede (NBR 15965-5) | no | 300 | 2467.21 | 0.042 | 0.558867 | 0.558867 | 0.0902292 | 0.0902292
Parede | Parede-interior-generico-in_loco-tijolo_maciço-140mm | EF_25_10 Walls (Uniclass 2015); Parede (Classificação ARCHICAD); 3E 14 02 00 Parede (NBR 15965-5) | no | 200 | 2437.29 | 0.0246 | 0.457189 | 0.457189 | 0.0593612 | 0.0593612

# IfcWall: Alvenaria Tijolo Maciço com Revestimento 28cm 280, Parede
In: Pavimento Térreo
Description: Parede-exterior-generico-in_loco-tijolo_maciço-280mm; Classification: EF_25_10 Walls (Uniclass 2015); 3E 14 02 00 Parede (NBR 15965-5); Parede (Classificação ARCHICAD)
Pset_WallCommon - AcousticRating: 0.00; LoadBearing: yes; IsExternal: yes
AC_Pset_RenovationAndPhasing - Renovation Status: Existing
BaseQuantities - Length: 5730 mm; Height: 1350 mm; Width: 280 mm; GrossFootprintArea: 1.5416 m2; NetFootprintArea: 1.5416 m2; GrossSideArea: 6.02134 m2; NetSideArea: 6.02134 m2; GrossVolume: 1.65034 m3; NetVolume: 1.65034 m3

# IfcWall: Concreto Armado - Estrutural 100 (2)
In: Primeiro Pavimento
Description: Empena-estrutural-generico-in_loco-concreto_armado-100mm; Classification: EF_25_10 Walls (Uniclass 2015); Parede (Classificação ARCHICAD); 3E 12 08 02 Estrutura de placas (NBR 15965-5); Material: Concreto Armado - Estrutural
Pset_WallCommon - AcousticRating: 0.00; LoadBearing: yes; IsExternal: yes
AC_Pset_RenovationAndPhasing - Renovation Status: Existing
Component Properties - Component 1, Tipo de Componente: Nenhum
BaseQuantities - Length: 11600 mm; Height: 4348.15 mm; Width: 100 mm; GrossFootprintArea: 1.15971 m2; NetFootprintArea: 1.15971 m2; GrossSideArea: 40.3075 m2; GrossVolume: 4.03075 m3
Component Quantities - Component 1, Espessura da Camada: 100 mm; Component 1, Largura do Componente Retangular: 100 mm
Name | Component 1, Carbono Incorporado | Component 1, Energia Incorporada (MJ) | NetSideArea (m2) = Component 1, Área Projetada Componente/Camada (m2) | NetVolume (m3) = Component 1, Volume da Camada/ Componente (m3) | Component 1, Massa (kg) | Component 1, Altura do Componente Retangular (mm) | Component 1, Área de Seção Transversal do Componente (m2)
Empena | 2341.06 (kgCO₂) | 22539.9 | 40.3075 | 4.03075 | 9673.8 | 4401.14 | 0.440114
Empena | 2277.45 (kgCO₂) | 21927.5 | 39.2123 | 3.92123 | 9410.95 | 4348.15 | 0.434815

# IfcWallStandardCase: Alvenaria Tijolo Maciço com Revestimento 10cm 100 (5)
In: Pavimento Térreo
Description: Parede-interior-generico-in_loco-tijolo_maciço-100mm; Classification: EF_25_10 Walls (Uniclass 2015); Parede (Classificação ARCHICAD); 3E 14 02 00 Parede (NBR 15965-5); Material: Reboco (1) 20 mm, Tijolo - Estrutural (1) 60 mm, Reboco (1) 20 mm
Pset_WallCommon - AcousticRating: 0.00; LoadBearing: yes; IsExternal: no
Component Properties - Component 1, Tipo de Componente: Acabamento; Component 2, Tipo de Componente: Núcleo; Component 3, Tipo de Componente: Acabamento
BaseQuantities - Width: 100 mm
Component Quantities - Component 1, Espessura da Camada: 20 mm; Component 1, Largura do Componente Retangular: 20 mm; Component 2, Espessura da Camada: 60 mm; Component 2, Largura do Componente Retangular: 60 mm; Component 3, Espessura da Camada: 20 mm; Component 3, Largura do Componente Retangular: 20 mm
Name | Renovation Status | Component 1, Carbono Incorporado | Component 1, Energia Incorporada (MJ) | Component 2, Carbono Incorporado | Component 2, Energia Incorporada (MJ) | Component 3, Carbono Incorporado | Component 3, Energia Incorporada (MJ) | Length (mm) | Height (mm) = Component 1, Altura do Componente Retangular (mm) = Component 2, Altura do Componente Retangular (mm) = Component 3, Altura do Componente Retangular (mm) | GrossFootprintArea (m2) = NetFootprintArea (m2) | GrossSideArea (m2) | NetSideArea (m2) | GrossVolume (m3) | NetVolume (m3) | Component 1, Massa (kg) | Component 1, Área Projetada Componente/Camada (m2) | Component 1, Área de Seção Transversal do Componente (m2) = Component 3, Área de Seção Transversal do Componente (m2) | Component 1, Volume da Camada/ Componente (m3) | Component 2, Massa (kg) | Component 2, Área Projetada Componente/Camada (m2) | Component 2, Área de Seção Transversal do Componente (m2) | Component 2, Volume da Camada/ Componente (m3) | Component 3, Massa (kg) | Component 3, Área Projetada Componente/Camada (m2) | Component 3, Volume da Camada/ Componente (m3)
Parede | Existing | 11.6982 (kgCO₂) | 161.975 | 76.4208 (kgCO₂) | 955.26 | 11.6171 (kgCO₂) | 160.852 | 2040 | 2550 | 0.2088 | 5.199 | 3.449 | 0.52524 | 0.35024 | 89.986 | 3.461 | 0.051 | 0.06922 | 318.42 | 3.538 | 0.153 | 0.21228 | 89.362 | 3.437 | 0.06874
Parede | To Be Demolished | 1.41452 (kgCO₂) | 19.5857 | 8.89789 (kgCO₂) | 111.224 | 1.25834 (kgCO₂) | 17.4231 | 1050 | 400 | 0.10133 | 0.395393 | 0.395393 | 0.0405321 | 0.0405321 | 10.8809 | 0.42 | 0.008 | 0.00836994 | 37.0745 | 0.416448 | 0.024 | 0.0247164 | 9.67952 | 0.373792 | 0.00744578
Parede | To Be Demolished | 2.10866 (kgCO₂) | 29.1968 | 12.7371 (kgCO₂) | 159.213 | 1.87757 (kgCO₂) | 25.9972 | 1581.02 | 400 | 0.14742 | 0.589679 | 0.589679 | 0.0589679 | 0.0589679 | 16.2205 | 0.62687 | 0.008 | 0.0124773 | 53.0711 | 0.598697 | 0.024 | 0.0353808 | 14.4429 | 0.558501 | 0.0111099
Parede | To Be Demolished | 0.779158 (kgCO₂) | 10.7883 | 4.38251 (kgCO₂) | 54.7813 | 0.596095 (kgCO₂) | 8.25362 | 593.908 | 400 | 0.050778 | 0.20344 | 0.20344 | 0.0203112 | 0.0203112 | 5.99352 | 0.232023 | 0.008 | 0.0046104 | 18.2604 | 0.207403 | 0.024 | 0.0121736 | 4.58535 | 0.177862 | 0.00352719
Parede | To Be Demolished | 0.64896 (kgCO₂) | 8.9856 | 3.8016 (kgCO₂) | 47.52 | 0.5408 (kgCO₂) | 7.488 | 500 | 400 | 0.044 | 0.176 | 0.176 | 0.0176 | 0.0176 | 4.992 | 0.192 | 0.008 | 0.00384 | 15.84 | 0.176 | 0.024 | 0.01056 | 4.16 | 0.16 | 0.0032

# IfcWallStandardCase: Alvenaria Tijolo Maciço com Revestimento 14cm 140 (13)
In: Pavimento Térreo
Material: Reboco (1) 20 mm, Tijolo - Estrutural (1) 100 mm, Reboco (1) 20 mm
Pset_WallCommon - AcousticRating: 0.00; LoadBearing: yes
AC_Pset_RenovationAndPhasing - Renovation Status: Existing
Component Properties - Component 1, Tipo de Componente: Acabamento; Component 2, Tipo de Componente: Núcleo; Component 3, Tipo de Componente: Acabamento
BaseQuantities - Width: 140 mm
Component Quantities - Component 1, Espessura da Camada: 20 mm; Component 1, Largura do Componente Retangular: 20 mm; Component 2, Espessura da Camada: 100 mm; Component 2, Largura do Componente Retangular: 100 mm; Component 3, Espessura da Camada: 20 mm; Component 3, Largura do Componente Retangular: 20 mm
Name | Description | Classification | IsExternal | Component 1, Carbono Incorporado | Component 1, Energia Incorporada (MJ) | Component 2, Carbono Incorporado | Component 2, Energia Incorporada (MJ) | Component 3, Carbono Incorporado | Component 3, Energia Incorporada (MJ) | Length (mm) | Height (mm) = Component 1, Altura do Componente Retangular (mm) = Component 2, Altura do Componente Retangular (mm) = Component 3, Altura do Componente Retangular (mm) | GrossFootprintArea (m2) = NetFootprintArea (m2) | GrossSideArea (m2) | NetSideArea (m2) | GrossVolume (m3) | NetVolume (m3) | Component 1, Massa (kg) | Component 1, Área Projetada Componente/Camada (m2) | Component 1, Área de Seção Transversal do Componente (m2) = Component 3, Área de Seção Transversal do Componente (m2) | Component 1, Volume da Camada/ Componente (m3) | Component 2, Massa (kg) | Component 2, Área Projetada Componente/Camada (m2) | Component 2, Área de Seção Transversal do Componente (m2) | Component 2, Volume da Camada/ Componente (m3) | Component 3, Massa (kg) | Component 3, Área Projetada Componente/Camada (m2) | Component 3, Volume da Camada/ Componente (m3)
Parede | Parede-exterior-generico-in_loco-tijolo_maciço-140mm | EF_25_10 Walls (Uniclass 2015); 3E 14 02 00 Parede (NBR 15965-5); Parede (Classificação ARCHICAD) | yes | 27.2563 (kgCO₂) | 377.395 | 289.08 (kgCO₂) | 3613.5 | 25.1607 (kgCO₂) | 348.379 | 4480 | 2550 | 0.5263 | 11.0605 | 7.7555 | 1.57612 | 1.11316 | 209.664 | 8.064 | 0.051 | 0.16128 | 1204.5 | 8.03 | 0.255 | 0.803 | 193.544 | 7.447 | 0.14888
Parede | Parede-exterior-generico-in_loco-tijolo_maciço-140mm | EF_25_10 Walls (Uniclass 2015); 3E 14 02 00 Parede (NBR 15965-5); Parede (Classificação ARCHICAD) | yes | 70.6927 (kgCO₂) | 978.822 | 728.172 (kgCO₂) | 9102.15 | 64.2301 (kgCO₂) | 889.34 | 13220 | 2550 | 1.8468 | 32.959 | 19.959 | 4.64106 | 2.82106 | 543.79 | 20.915 | 0.051 | 0.4183 | 3034.05 | 20.227 | 0.255 | 2.0227 | 494.078 | 19.003 | 0.38006
Parede | Parede-interior-generico-in_loco-tijolo_maciço-140mm | EF_25_10 Walls (Uniclass 2015); Parede (Classificação ARCHICAD); 3E 14 02 00 Parede (NBR 15965-5) | no | 25.3906 (kgCO₂) | 351.562 | 286.956 (kgCO₂) | 3586.95 | 24.1839 (kgCO₂) | 334.854 | 3660 | 2550 | 0.5164 | 8.9505 | 7.3335 | 1.31682 | 1.09044 | 195.312 | 7.512 | 0.051 | 0.15024 | 1195.65 | 7.971 | 0.255 | 0.7971 | 186.03 | 7.155 | 0.1431
Parede | Parede-interior-generico-in_loco-tijolo_maciço-140mm | EF_25_10 Walls (Uniclass 2015); Parede (Classificação ARCHICAD); 3E 14 02 00 Parede (NBR 15965-5) | no | 8.58013 (kgCO₂) | 118.802 | 95.022 (kgCO₂) | 1187.78 | 8.58013 (kgCO₂) | 118.802 | 1540 | 2550 | 0.1678 | 3.912 | 2.5385 | 0.55778 | 0.36549 | 66.001 | 2.5385 | 0.051 | 0.05077 | 395.925 | 2.6395 | 0.255 | 0.26395 | 66.001 | 2.5385 | 0.05077
Parede | Parede-interior-generico-in_loco-tijolo_maciço-140mm | EF_25_10 Walls (Uniclass 2015); Parede (Classificação ARCHICAD); 3E 14 02 00 Parede (NBR 15965-5) | no | 52.1754 (kgCO₂) | 722.428 | 596.106 (kgCO₂) | 7451.33 | 54.0716 (kgCO₂) | 748.683 | 6900 | 2550 | 0.9962 | 17.544 | 15.717 | 2.54031 | 2.28453 | 401.349 | 15.4365 | 0.051 | 0.30873 | 2483.78 | 16.5585 | 0.255 | 1.65585 | 415.935 | 15.9975 | 0.31995
Parede | Parede-exterior-generico-in_loco-tijolo_maciço-140mm | EF_25_10 Walls (Uniclass 2015); 3E 14 02 00 Parede (NBR 15965-5); Parede (Classificação ARCHICAD) | yes | 15.2708 (kgCO₂) | 211.442 | 144.468 (kgCO₂) | 1805.85 | 13.2226 (kgCO₂) | 183.082 | 1680 | 2550 | 0.2244 | 4.215 | 4.215 | 0.5699 | 0.5699 | 117.468 | 4.518 | 0.051 | 0.09036 | 601.95 | 4.013 | 0.255 | 0.4013 | 101.712 | 3.912 | 0.07824
Parede | Parede-interior-generico-in_loco-tijolo_maciço-140mm | EF_25_10 Walls (Uniclass 2015); Parede (Classificação ARCHICAD); 3E 14 02 00 Parede (NBR 15965-5) | no | 13.0147 (kgCO₂) | 180.203 | 142.29 (kgCO₂) | 1778.62 | 13.0147 (kgCO₂) | 180.203 | 1510 | 2550 | 0.2154 | 3.8505 | 3.8505 | 0.54927 | 0.54927 | 100.113 | 3.8505 | 0.051 | 0.07701 | 592.875 | 3.9525 | 0.255 | 0.39525 | 100.113 | 3.8505 | 0.07701
Parede | Parede-interior-generico-in_loco-tijolo_maciço-140mm | EF_25_10 Walls (Uniclass 2015); Parede (Classificação ARCHICAD); 3E 14 02 00 Parede (NBR 15965-5) | no | 4.3095 (kgCO₂) | 59.67 | 45.9 (kgCO₂) | 573.75 | 4.3095 (kgCO₂) | 59.67 | 500 | 2550 | 0.07 | 1.275 | 1.275 | 0.1785 | 0.1785 | 33.15 | 1.275 | 0.051 | 0.0255 | 191.25 | 1.275 | 0.255 | 0.1275 | 33.15 | 1.275 | 0.0255
Parede | Parede-interior-generico-in_loco-tijolo_maciço-140mm | EF_25_10 Walls (Uniclass 2015); Parede (Classificação ARCHICAD); 3E 14 02 00 Parede (NBR 15965-5) | no | 12.5837 (kgCO₂) | 174.236 | 150.552 (kgCO₂) | 1881.9 | 14.3075 (kgCO₂) | 198.104 | 1640 | 2550 | 0.2264 | 3.978 | 3.978 | 0.57732 | 0.57732 | 96.798 | 3.723 | 0.051 | 0.07446 | 627.3 | 4.182 | 0.255 | 0.4182 | 110.058 | 4.233 | 0.08466
Parede | Parede-interior-generico-in_loco-tijolo_maciço-140mm | EF_25_10 Walls (Uniclass 2015); Parede (Classificação ARCHICAD); 3E 14 02 00 Parede (NBR 15965-5) | no | 4.34221 (kgCO₂) | 60.123 | 48.0844 (kgCO₂) | 601.055 | 5.37649 (kgCO₂) | 74.4438 | 573.796 | 2550 | 0.0749314 | 1.43768 | 1.43768 | 0.191075 | 0.191075 | 33.4016 | 1.28468 | 0.051 | 0.0256936 | 200.352 | 1.33568 | 0.255 | 0.133568 | 41.3576 | 1.59068 | 0.0318136
Parede | Parede-interior-generico-in_loco-tijolo_maciço-140mm | EF_25_10 Walls (Uniclass 2015); Parede (Classificação ARCHICAD); 3E 14 02 00 Parede (NBR 15965-5) | no | 7.67091 (kgCO₂) | 106.213 | 92.718 (kgCO₂) | 1158.97 | 8.70519 (kgCO₂) | 120.533 | 940 | 2550 | 0.139 | 2.4225 | 2.4225 | 0.35445 | 0.35445 | 59.007 | 2.2695 | 0.051 | 0.04539 | 386.325 | 2.5755 | 0.255 | 0.25755 | 66.963 | 2.5755 | 0.05151
Parede | Parede-interior-generico-in_loco-tijolo_maciço-140mm | EF_25_10 Walls (Uniclass 2015); Parede (Classificação ARCHICAD); 3E 14 02 00 Parede (NBR 15965-5) | no | 4.48188 (kgCO₂) | 62.0568 | 40.392 (kgCO₂) | 504.9 | 4.48188 (kgCO₂) | 62.0568 | 540 | 2550 | 0.0648 | 1.326 | 1.326 | 0.16524 | 0.16524 | 34.476 | 1.326 | 0.051 | 0.02652 | 168.3 | 1.122 | 0.255 | 0.1122 | 34.476 | 1.326 | 0.02652
Parede | Parede-exterior-generico-in_loco-tijolo_maciço-140mm | EF_25_10 Walls (Uniclass 2015); 3E 14 02 00 Parede (NBR 15965-5); Parede (Classificação ARCHICAD) | yes | 20.6349 (kgCO₂) | 285.714 | 200.124 (kgCO₂) | 2501.55 | 18.5765 (kgCO₂) | 257.213 | 3710 | 2100 | 0.5072 | 7.7805 | 5.8005 | 1.06512 | 0.78792 | 158.73 | 6.105 | 0.042 | 0.1221 | 833.85 | 5.559 | 0.21 | 0.5559 | 142.896 | 5.496 | 0.10992

# IfcWallStandardCase: Alvenaria Tijolo Maciço com Revestimento 28cm 280 (10)
In: Pavimento Térreo
Material: Reboco 20 mm, Tijolo - Estrutural 240 mm, Reboco 20 mm
Pset_WallCommon - AcousticRating: 0.00; LoadBearing: yes
AC_Pset_RenovationAndPhasing - Renovation Status: Existing
Component Properties - Component 1, Tipo de Componente: Acabamento; Component 2, Tipo de Componente: Núcleo; Component 3, Tipo de Componente: Acabamento
BaseQuantities - Width: 280 mm
Component Quantities - Component 1, Espessura da Camada: 20 mm; Component 1, Largura do Componente Retangular: 20 mm; Component 2, Espessura da Camada: 240 mm; Component 2, Largura do Componente Retangular: 240 mm; Component 3, Espessura da Camada: 20 mm; Component 3, Largura do Componente Retangular: 20 mm
Name | Description | Classification | IsExternal | Component 1, Carbono Incorporado | Component 1, Energia Incorporada (MJ) | Component 2, Carbono Incorporado | Component 2, Energia Incorporada (MJ) | Component 3, Carbono Incorporado | Component 3, Energia Incorporada (MJ) | Length (mm) | Height (mm) = Component 1, Altura do Componente Retangular (mm) = Component 2, Altura do Componente Retangular (mm) = Component 3, Altura do Componente Retangular (mm) | GrossFootprintArea (m2) = NetFootprintArea (m2) | GrossSideArea (m2) | NetSideArea (m2) | GrossVolume (m3) | NetVolume (m3) | Component 1, Massa (kg) | Component 1, Área Projetada Componente/Camada (m2) | Component 1, Área de Seção Transversal do Componente (m2) = Component 3, Área de Seção Transversal do Componente (m2) | Component 1, Volume da Camada/ Componente (m3) | Component 2, Massa (kg) | Component 2, Área Projetada Componente/Camada (m2) | Component 2, Área de Seção Transversal do Componente (m2) | Component 2, Volume da Camada/ Componente (m3) | Component 3, Massa (kg) | Component 3, Área Projetada Componente/Camada (m2) | Component 3, Volume da Camada/ Componente (m3)
Parede | Parede-exterior-generico-in_loco-tijolo_maciço-280mm | EF_25_10 Walls (Uniclass 2015); 3E 14 02 00 Parede (NBR 15965-5); Parede (Classificação ARCHICAD) | yes | 40.9808 (kgCO₂) | 567.427 | 1100.43 (kgCO₂) | 13755.4 | 41.4337 (kgCO₂) | 573.698 | 5620 | 2550 | 1.6204 | 14.2285 | 12.1915 | 4.11478 | 3.54442 | 315.237 | 12.1245 | 0.051 | 0.24249 | 4585.14 | 12.7365 | 0.612 | 3.05676 | 318.721 | 12.2585 | 0.24517
Parede | Parede-exterior-generico-in_loco-tijolo_maciço-280mm | EF_25_10 Walls (Uniclass 2015); 3E 14 02 00 Parede (NBR 15965-5); Parede (Classificação ARCHICAD) | yes | 40.3285 (kgCO₂) | 558.394 | 1055.66 (kgCO₂) | 13195.8 | 40.2524 (kgCO₂) | 557.341 | 5100 | 2550 | 1.3913 | 11.9202 | 11.9202 | 3.4092 | 3.4092 | 310.219 | 11.9315 | 0.051 | 0.23863 | 4398.59 | 12.497 | 0.612 | 2.93239 | 309.634 | 11.909 | 0.23818
Parede | Parede-exterior-generico-in_loco-tijolo_maciço-280mm | EF_25_10 Walls (Uniclass 2015); 3E 14 02 00 Parede (NBR 15965-5); Parede (Classificação ARCHICAD) | yes | 29.9147 (kgCO₂) | 414.203 | 766.282 (kgCO₂) | 9578.52 | 28.8179 (kgCO₂) | 399.017 | 3690 | 2550 | 1.013 | 8.68825 | 8.68825 | 2.47609 | 2.47609 | 230.113 | 8.8505 | 0.051 | 0.17701 | 3192.84 | 8.869 | 0.612 | 2.12856 | 221.676 | 8.526 | 0.17052
Parede | Parede-exterior-generico-in_loco-tijolo_maciço-280mm | EF_25_10 Walls (Uniclass 2015); 3E 14 02 00 Parede (NBR 15965-5); Parede (Classificação ARCHICAD) | yes | 57.5837 (kgCO₂) | 797.313 | 1442.77 (kgCO₂) | 18034.6 | 58.6177 (kgCO₂) | 811.629 | 7560 | 2550 | 2.01271 | 18.5896 | 17.1896 | 5.08728 | 4.69528 | 442.952 | 17.0366 | 0.051 | 0.340732 | 6011.54 | 17.5465 | 0.612 | 4.00769 | 450.905 | 17.3425 | 0.34685
Parede | Parede-interior-generico-in_loco-tijolo_maciço-280mm | EF_25_10 Walls (Uniclass 2015); Parede (Classificação ARCHICAD); 3E 14 02 00 Parede (NBR 15965-5) | no | 25.7691 (kgCO₂) | 356.803 | 667.526 (kgCO₂) | 8344.08 | 25.7691 (kgCO₂) | 356.803 | 3480 | 2550 | 0.984 | 8.874 | 7.624 | 2.5092 | 2.1592 | 198.224 | 7.624 | 0.051 | 0.15248 | 2781.36 | 7.726 | 0.612 | 1.85424 | 198.224 | 7.624 | 0.15248
Parede | Parede-exterior-generico-in_loco-tijolo_maciço-280mm | EF_25_10 Walls (Uniclass 2015); 3E 14 02 00 Parede (NBR 15965-5); Parede (Classificação ARCHICAD) | yes | 9.04802 (kgCO₂) | 125.28 | 228.954 (kgCO₂) | 2861.92 | 7.86164 (kgCO₂) | 108.854 | 1842.91 | 1350 | 0.545215 | 2.50143 | 2.50143 | 0.73604 | 0.73604 | 69.6002 | 2.67693 | 0.027 | 0.0535386 | 953.975 | 2.64993 | 0.324 | 0.635983 | 60.4742 | 2.32593 | 0.0465186
Parede | Parede-exterior-generico-in_loco-tijolo_maciço-280mm | EF_25_10 Walls (Uniclass 2015); 3E 14 02 00 Parede (NBR 15965-5); Parede (Classificação ARCHICAD) | yes | 10.6347 (kgCO₂) | 147.249 | 241.519 (kgCO₂) | 3018.98 | 8.26191 (kgCO₂) | 114.396 | 2070.63 | 1350 | 0.579777 | 2.79535 | 2.79535 | 0.782699 | 0.782699 | 81.8052 | 3.14635 | 0.027 | 0.0629271 | 1006.33 | 2.79535 | 0.324 | 0.670885 | 63.5532 | 2.44435 | 0.0488871
Parede | Parede-exterior-generico-in_loco-tijolo_maciço-280mm | EF_25_10 Walls (Uniclass 2015); 3E 14 02 00 Parede (NBR 15965-5); Parede (Classificação ARCHICAD) | yes | 72.7342 (kgCO₂) | 1007.09 | 1828.92 (kgCO₂) | 22861.4 | 70.3615 (kgCO₂) | 974.236 | 15680 | 1350 | 4.3904 | 21.168 | 21.168 | 5.92704 | 5.92704 | 559.494 | 21.519 | 0.027 | 0.43038 | 7620.48 | 21.168 | 0.324 | 5.08032 | 541.242 | 20.817 | 0.41634
Parede | Parede-exterior-generico-in_loco-tijolo_maciço-280mm | EF_25_10 Walls (Uniclass 2015); 3E 14 02 00 Parede (NBR 15965-5); Parede (Classificação ARCHICAD) | yes | 32.9934 (kgCO₂) | 456.831 | 813.055 (kgCO₂) | 10163.2 | 30.6206 (kgCO₂) | 423.978 | 6970.63 | 1350 | 1.95178 | 9.41035 | 9.41035 | 2.6349 | 2.6349 | 253.795 | 9.76135 | 0.027 | 0.195227 | 3387.73 | 9.41035 | 0.324 | 2.25848 | 235.543 | 9.05935 | 0.181187
Parede | Parede-exterior-generico-in_loco-tijolo_maciço-280mm | EF_25_10 Walls (Uniclass 2015); 3E 14 02 00 Parede (NBR 15965-5); Parede (Classificação ARCHICAD) | yes | 18.5447 (kgCO₂) | 256.772 | 476.115 (kgCO₂) | 5951.44 | 18.5447 (kgCO₂) | 256.772 | 4064.14 | 1350 | 1.14276 | 5.48659 | 5.48659 | 1.54201 | 1.54201 | 142.651 | 5.48659 | 0.027 | 0.109732 | 1983.81 | 5.51059 | 0.324 | 1.32254 | 142.651 | 5.48659 | 0.109732

# IfcWindow: Janela 23 (2)
In: Primeiro Pavimento
Type - OperationType: SINGLE_PANEL; ParameterTakesPrecedence: no; Sizeable: no
Type - Window Lining Properties - LiningDepth: 50 mm; LiningThickness: 35 mm
Type - Window Panel Properties - Panel 1 - OperationType: TOPHUNG; PanelPosition: MIDDLE; FrameDepth: 50 mm; FrameThickness: 50 mm
Description: Janela-basculante-generico-generico-metal-74cm-74cm; OverallHeight: 740 mm; OverallWidth: 740 mm; Classification: 3E 20 04 02 Janelas (NBR 15965-5); EF_25_30 Doors and windows (Uniclass 2015); Janela (Classificação ARCHICAD)
Pset_WindowCommon - ThermalTransmittance: 0; GlazingAreaFraction: 0.3844; IsExternal: yes
AC_Pset_RenovationAndPhasing - Renovation Status: Existing
BaseQuantities - GrossArea: 0.5476 m2; Height: 740 mm; Width: 740 mm; Perimeter: 2960 mm; Area: 0.5476 m2; Volume: 0.0098975 m3; Depth: 100 mm; NetVolume: 0.0098975 m3
Name
J07 | Component Quantities - Component 1, Volume da Camada/ Componente: 0.0098975 m3
J15

# IfcWindow: Janela Dupla Dupla-Guilhotina 23 (4)
In: Primeiro Pavimento
Type - OperationType: USERDEFINED; ParameterTakesPrecedence: no; Sizeable: no
Description: Janela-dupla_guilhotina-generico-generico-madeira-285cm-120cm; OverallHeight: 1200 mm; OverallWidth: 2850 mm; Classification: 3E 20 04 02 Janelas (NBR 15965-5); EF_25_30 Doors and windows (Uniclass 2015); Janela (Classificação ARCHICAD)
Pset_WindowCommon - ThermalTransmittance: 0; GlazingAreaFraction: 2.4941; IsExternal: yes
AC_Pset_RenovationAndPhasing - Renovation Status: Existing
BaseQuantities - GrossArea: 3.42 m2; Height: 1200 mm; Width: 2850 mm; Perimeter: 8100 mm; Area: 3.42 m2; Volume: 0.096691 m3; Depth: 140 mm; NetVolume: 0.096691 m3
Name
J23 | Component Quantities - Component 1, Volume da Camada/ Componente: 0.096691 m3
J24
J25
J26

# IfcWindow: Janela Multi-Caixilho Vertical 23 (8)
In: Pavimento Térreo
Type - OperationType: DOUBLE_PANEL_HORIZONTAL; ParameterTakesPrecedence: no; Sizeable: no
Type - Window Lining Properties - LiningDepth: 40 mm; LiningThickness: 35 mm; TransomThickness: 35 mm; FirstTransomOffset: 0.5
Type - Window Panel Properties - Panel 1 - OperationType: FIXEDCASEMENT; PanelPosition: TOP
Type - Window Panel Properties - Panel 2 - OperationType: FIXEDCASEMENT; PanelPosition: BOTTOM
OverallHeight: 400 mm; Classification: 3E 20 04 02 Janelas (NBR 15965-5); EF_25_30 Doors and windows (Uniclass 2015); Janela (Classificação ARCHICAD)
Pset_WindowCommon - ThermalTransmittance: 0; IsExternal: yes
AC_Pset_RenovationAndPhasing - Renovation Status: Existing
BaseQuantities - Depth: 140 mm
Name | Description | OverallWidth (mm) | GlazingAreaFraction | GrossArea (m2) = Area (m2) | Height (mm) | Width (mm) | Perimeter (mm) | Volume (m3) = NetVolume (m3)
J04 | Janela-multi_caixilho-generico-generico-metal-90cm-40cm | 975 | 0.266975 | 0.39 | 400 | 975 | 2750 | 0.004921 | Component Quantities - Component 1, Volume da Camada/ Componente: 0.004921 m3
J05 | Janela-multi_caixilho-generico-generico-metal-65cm-40cm | 650 | 0.1711 | 0.26 | 400 | 650 | 2100 | 0.003556 | Component Quantities - Component 1, Volume da Camada/ Componente: 0.003556 m3
J13 | Janela-multi_caixilho-generico-generico-metal-65cm-40cm | 650 | 0.1711 | 0.26 | 400 | 650 | 2100 | 0.003556
J08 | Janela-multi_caixilho-generico-generico-metal-90cm-40cm | 975 | 0.266975 | 0.39 | 400 | 975 | 2750 | 0.004921
J09 | Janela-multi_caixilho-generico-generico-metal-90cm-40cm | 975 | 0.266975 | 0.39 | 400 | 975 | 2750 | 0.004921
J10 | Janela-multi_caixilho-generico-generico-metal-90cm-40cm | 900 | 0.24485 | 0 | 0 | 0 | 0 | 0.004606 | Component Quantities - Component 1, Volume da Camada/ Componente: 0.004606 m3
J11 | Janela-multi_caixilho-generico-generico-metal-90cm-40cm | 900 | 0.24485 | 0 | 0 | 0 | 0 | 0.004606
J12 | Janela-multi_caixilho-generico-generico-metal-90cm-40cm | 900 | 0.24485 | 0 | 0 | 0 | 0 | 0.004606

# IfcWindow: Janela Multi-Caixilho Vertical 23 (8)
In: Pavimento Térreo
Type - OperationType: TRIPLE_PANEL_HORIZONTAL; ParameterTakesPrecedence: no; Sizeable: no
Type - Window Lining Properties - LiningDepth: 50 mm; LiningThickness: 35 mm; TransomThickness: 35 mm; FirstTransomOffset: 0.336436; SecondTransomOffset: 0.663564
Type - Window Panel Properties - Panel 1 - OperationType: FIXEDCASEMENT; PanelPosition: TOP
Type - Window Panel Properties - Panel 2 - OperationType: FIXEDCASEMENT; PanelPosition: MIDDLE
Type - Window Panel Properties - Panel 3 - OperationType: FIXEDCASEMENT; PanelPosition: BOTTOM
Description: Janela-multi_caixilho-generico-generico-metal-170cm-188cm; OverallHeight: 1880 mm; OverallWidth: 1700 mm; Classification: 3E 20 04 02 Janelas (NBR 15965-5); EF_25_30 Doors and windows (Uniclass 2015); Janela (Classificação ARCHICAD)
Pset_WindowCommon - ThermalTransmittance: 0; GlazingAreaFraction: 2.8362; IsExternal: yes
AC_Pset_RenovationAndPhasing - Renovation Status: Existing
BaseQuantities - GrossArea: 0 m2; Height: 0 mm; Width: 0 mm; Perimeter: 0 mm; Area: 0 m2; Volume: 0.01799 m3; Depth: 140 mm; NetVolume: 0.01799 m3
Name
J02 | Component Quantities - Component 1, Volume da Camada/ Componente: 0.01799 m3
J16
J17
J18
J19
J20
J21
J22

# IfcWindow: Janela Multi-Caixilho Vertical 23 (2)
In: Pavimento Térreo
Type - OperationType: TRIPLE_PANEL_HORIZONTAL; ParameterTakesPrecedence: no; Sizeable: no
Type - Window Lining Properties - LiningDepth: 50 mm; LiningThickness: 35 mm; TransomThickness: 35 mm; FirstTransomOffset: 0.341667; SecondTransomOffset: 0.658333
Type - Window Panel Properties - Panel 1 - OperationType: FIXEDCASEMENT; PanelPosition: TOP
Type - Window Panel Properties - Panel 2 - OperationType: FIXEDCASEMENT; PanelPosition: MIDDLE
Type - Window Panel Properties - Panel 3 - OperationType: FIXEDCASEMENT; PanelPosition: BOTTOM
Description: Janela-multi_caixilho-generico-generico-metal-100cm-70cm; OverallHeight: 700 mm; OverallWidth: 1000 mm; Classification: 3E 20 04 02 Janelas (NBR 15965-5); EF_25_30 Doors and windows (Uniclass 2015); Janela (Classificação ARCHICAD)
Pset_WindowCommon - ThermalTransmittance: 0; GlazingAreaFraction: 0.5208; IsExternal: yes
AC_Pset_RenovationAndPhasing - Renovation Status: Existing
BaseQuantities - GrossArea: 0.7 m2; Height: 700 mm; Width: 1000 mm; Perimeter: 3400 mm; Area: 0.7 m2; Volume: 0.00896 m3; Depth: 280 mm; NetVolume: 0.00896 m3
Name
J06 | Component Quantities - Component 1, Volume da Camada/ Componente: 0.00896 m3
J14

# IfcWindow: Janela Tripla 23, J03
In: Pavimento Térreo
Type - OperationType: TRIPLE_PANEL_VERTICAL; ParameterTakesPrecedence: no; Sizeable: no
Type - Window Lining Properties - LiningDepth: 50 mm; LiningThickness: 35 mm; MullionThickness: 35 mm; FirstMullionOffset: 0.335985; SecondMullionOffset: 0.664015
Type - Window Panel Properties - Panel 1 - OperationType: FIXEDCASEMENT; PanelPosition: RIGHT
Type - Window Panel Properties - Panel 2 - OperationType: FIXEDCASEMENT; PanelPosition: MIDDLE
Type - Window Panel Properties - Panel 3 - OperationType: FIXEDCASEMENT; PanelPosition: LEFT
Description: Janela-tripla-generico-generico-metal-220cm-90cm; OverallHeight: 900 mm; OverallWidth: 2200 mm; Classification: 3E 20 04 02 Janelas (NBR 15965-5); EF_25_30 Doors and windows (Uniclass 2015); Janela (Classificação ARCHICAD)
Pset_WindowCommon - ThermalTransmittance: 0; GlazingAreaFraction: 1.7098; IsExternal: yes
AC_Pset_RenovationAndPhasing - Renovation Status: Existing
BaseQuantities - GrossArea: 1.98 m2; Height: 900 mm; Width: 2200 mm; Perimeter: 6200 mm; Area: 1.98 m2; Volume: 0.01351 m3; Depth: 140 mm; NetVolume: 0.01351 m3
Component Quantities - Component 1, Volume da Camada/ Componente: 0.01351 m3
